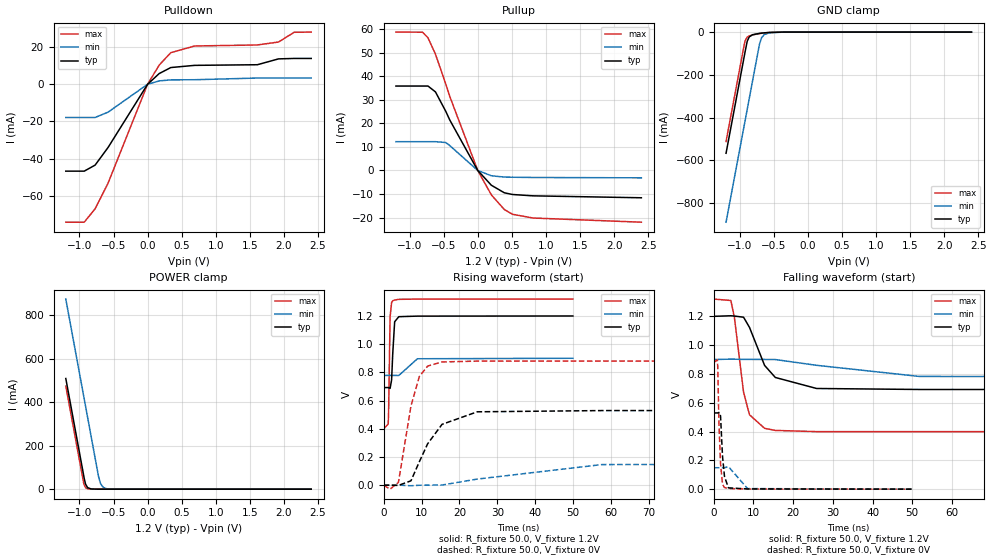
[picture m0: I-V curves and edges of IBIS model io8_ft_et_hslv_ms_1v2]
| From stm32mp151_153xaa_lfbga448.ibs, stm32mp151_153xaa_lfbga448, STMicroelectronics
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[Model]   io8_ft_et_hslv_ms_1v2
Model_type I/O
Polarity   Non-Inverting
Enable   Active-Low
| CAP_THRESHOLD on pad IOFT is "UDTCAPC" :
| Rising=20.00f vddiom   Falling=80.00f vddiom
| C_comp min and max val. don't necessarily correlate with the min and max pvt
| but are the smallest and greatest pad capacitance found.
| var   typ   min   max
C_comp   3.10945pF  3.08840pF  3.12935pF
|C_comp_pullup   1.82175pF  1.58940pF  1.75355pF
|C_comp_pulldown   1.28770pF  1.49900pF  1.37580pF
Vinl = 360.0mV
Vinh = 792.0mV
Vmeas = 600.0mV   | Reference voltage for timing measurements
Cref  = 50.0pF   | Timing specification test load capacitance value
Rref  = 100.0MOhm   | Timing specification test load resistance value
Vref  = 0V   | Timing specification test load voltage
[Model Spec]
| TIME_THRESHOLD on pin ZIV11 is "CMOS" :
| Rising=40.00f vdd   Falling=60.00f vdd
Vinl 463.60000mV 362.60000mV 506.60000mV
Vinh 741.40000mV 545.40000mV 817.40000mV
| variable   typ   min   max
[Temperature Range] 25.0 140.0 -40.0
| variable   typ   min   max
[Voltage Range] 1.2V 900.0mV 1.32V
| variable   typ   min   max
[POWER Clamp Reference] 1.2V 900.0mV 1.32V
| variable   typ   min   max
[GND Clamp Reference] 0V 0V 0V
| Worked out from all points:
|   slope of the pulldown table from 0 to 0.18 V, typ, clamps not added: 30 ohm
|   slope of the pullup table from 0 to 0.18 V, typ, clamps not added: 31.1 ohm
|   GND clamp passes 1 mA (typ) near -0.52 V on its own axis
|   POWER clamp passes 1 mA (typ) near -0.83 V on its own axis
|   rising waveform, R_fixture 50.0, V_fixture 1.2V: 20-80 % time 465ps typ, 1.29ns min, 300ps max; typ from 0.692 V to 1.2 V
|   falling waveform, R_fixture 50.0, V_fixture 1.2V: 20-80 % time 5.37ns typ, 13.1ns min, 2.71ns max; typ from 1.2 V to 0.692 V
|   rising waveform, R_fixture 50.0, V_fixture 0V: 20-80 % time 6.6ns typ, 15.4ns min, 3.56ns max; typ from 0 V to 0.529 V
|   falling waveform, R_fixture 50.0, V_fixture 0V: 20-80 % time 755ps typ, 1.48ns min, 602ps max; typ from 0.529 V to 0 V
[POWER Clamp]
-1.2V     508.8mA    874.1mA    473.5mA
-940mV    66.83mA    432.1mA    31.5mA
-930mV    49.83mA    415.1mA    19.15mA
-910mV    22.88mA    381.1mA    7.077mA
-880mV    7.117mA    330.1mA    1.59mA
-830mV    1.017mA    245.1mA    132uA
-720mV    14.05uA    58.12mA    554nA
-690mV    4.373uA    25.03mA    124.8nA
-650mV    922.5nA    8.136mA    17.23nA
-600mV    132.6nA    1.998mA    1.565nA
-490mV    2.857nA    90.92uA    111.8pA
2.4V      0A         0A         0A
[GND Clamp]
-1.2V     -567.2mA   -889.7mA   -512.2mA
-930mV    -108.2mA   -430.7mA   -53.23mA
-920mV    -91.21mA   -413.7mA   -40.49mA
-890mV    -43.51mA   -362.7mA   -23.59mA
-860mV    -22.57mA   -311.7mA   -17.89mA
-810mV    -12.11mA   -226.7mA   -13.23mA
-710mV    -6.053mA   -57.05mA   -7.064mA
-680mV    -4.908mA   -27.37mA   -5.632mA
-640mV    -3.605mA   -11.51mA   -3.985mA
-560mV    -1.665mA   -3.218mA   -1.61mA
-360mV    -34.72uA   -209.4uA   -9.248uA
2.4V      3.415nA    1.206uA    162.7pA
| variable   typ   min   max
[Pullup Reference] 1.2V 900.0mV 1.32V
| variable   typ   min   max
[Pulldown Reference] 0V 0V 0V
[Pullup]
-1.2V     35.8mA     12.19mA    58.69mA
-810mV    35.8mA     12.19mA    58.65mA
-730mV    35.8mA     12.19mA    56.27mA
-620mV    33.31mA    12.19mA    49.33mA
-470mV    25.13mA    11.85mA    36.73mA
-410mV    21.38mA    10.54mA    31.38mA
0V        5.9pA      1.254nA    2.839pA
200mV     -6.29mA    -2.269mA   -10.38mA
390mV     -9.484mA   -2.821mA   -16.59mA
510mV     -10.21mA   -2.888mA   -18.61mA
810mV     -10.78mA   -2.99mA    -20.19mA
2.4V      -11.6mA    -3.14mA    -21.96mA
[Pulldown]
-1.2V     -46.7mA    -17.86mA   -74.13mA
-930mV    -46.7mA    -17.86mA   -74.13mA
-770mV    -43.45mA   -17.86mA   -66.94mA
-580mV    -33.98mA   -14.99mA   -53.18mA
0V        0A         -6pA       0A
170mV     5.742mA    1.791mA    10.3mA
340mV     8.972mA    2.348mA    16.97mA
690mV     10.15mA    2.431mA    20.56mA
1.61V     10.49mA    3.333mA    21.11mA
1.92V     13.63mA    3.333mA    22.69mA
2.15V     13.87mA    3.333mA    27.93mA
2.4V      13.87mA    3.333mA    28.03mA
[Ramp]
dV/dt_r 317.40596mV/6.59553ns 89.2175mV/15.3922ns 528.1255mV/3.55691ns
dV/dt_f 304.66315mV/5.36712ns 73.16965mV/13.1332ns 552.41044mV/2.71068ns
R_load = 50.0
| Removed startup time: 0s 0s 0s  .
| Removed end time: 49.9ns.
[Rising Waveform]
R_fixture   = 50.0
V_fixture   = 1.2V
V_fixture_min = 900.0mV
V_fixture_max = 1.32V
0s        692.2mV    778mV      399.3mV
1.2ns     692.3mV    778.1mV    433.3mV
1.3ns     692.6mV    778.1mV    511.1mV
1.7ns     686.1mV    778.1mV    1.195V
2.1ns     747.2mV    778.1mV    1.296V
2.4ns     933.5mV    778.1mV    1.308V
2.9ns     1.159V     778.1mV    1.313V
4ns       1.195V     778mV      1.318V
8.9ns     1.199V     896.5mV    1.32V
49.9ns    1.2V       900mV      1.32V
| Removed startup time: 0s 0s 0s  .
| Removed end time: 299.9ns.
[Falling Waveform]
R_fixture   = 50.0
V_fixture   = 1.2V
V_fixture_min = 900.0mV
V_fixture_max = 1.32V
0s        1.2V       900mV      1.32V
4.3ns     1.204V     903mV      1.31V
5.2ns     1.202V     902.6mV    1.192V
7.5ns     1.194V     900.9mV    673mV
9ns       1.123V     901mV      516.6mV
12.8ns    859.3mV    900.7mV    422.3mV
15.5ns    775.6mV    900mV      407.9mV
25.9ns    699.1mV    860mV      399.5mV
51.8ns    692.2mV    782.7mV    399.3mV
299.9ns   692.2mV    778mV      399.3mV
| Removed startup time: 0s 0s 0s  .
| Removed end time: 299.9ns.
[Rising Waveform]
R_fixture   = 50.0
V_fixture   = 0V
V_fixture_min = 0V
V_fixture_max = 0V
0s        -85.77nV   237.3nV    -3.852uV
1.7ns     -652.7uV   362.2nV    -28.64mV
3.9ns     -1.908mV   141.5uV    19.39mV
7.2ns     30.56mV    -4.46mV    561.3mV
9.4ns     165.2mV    -926.5uV   770mV
11.6ns    293.1mV    96.9uV     844.4mV
15.4ns    431.3mV    770.9uV    873.9mV
24.7ns    520.2mV    43.02mV    879.9mV
57.6ns    528.9mV    146mV      880.2mV
299.9ns   529mV      148.7mV    880.2mV
| Removed startup time: 0s 0s 0s  .
| Removed end time: 49.9ns.
[Falling Waveform]
R_fixture   = 50.0
V_fixture   = 0V
V_fixture_min = 0V
V_fixture_max = 0V
0s        529mV      148.7mV    880.2mV
900ps     529.3mV    148.8mV    897.5mV
1ns       529.1mV    148.8mV    851.3mV
1.3ns     532.9mV    148.8mV    460.2mV
1.7ns     509.5mV    148.8mV    179.3mV
2.2ns     229.8mV    148.8mV    34.35mV
2.7ns     87.26mV    148.6mV    11.11mV
3.7ns     8.998mV    156.4mV    4.552mV
8.5ns     1.686mV    3.997mV    521.5uV
49.9ns    453.1nV    28.7uV     -108.1nV
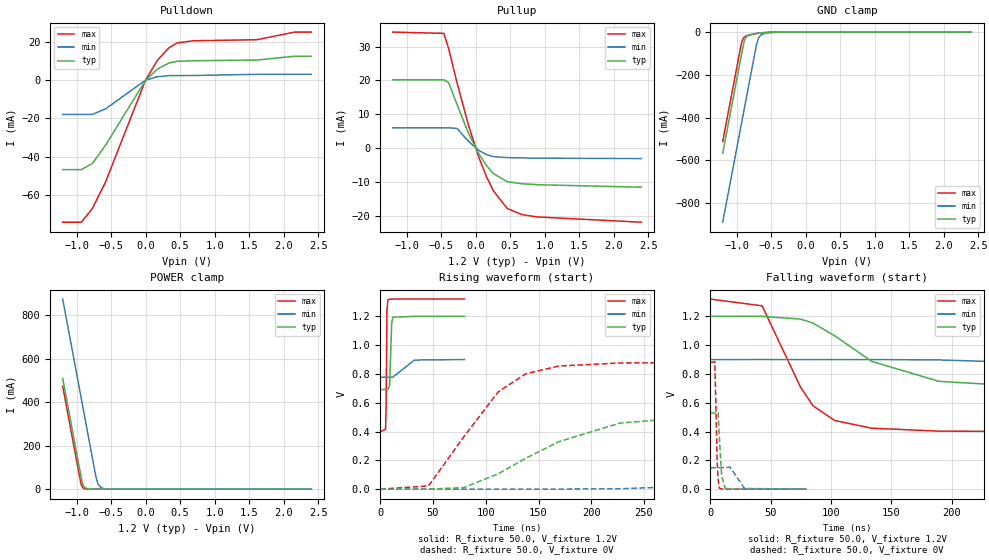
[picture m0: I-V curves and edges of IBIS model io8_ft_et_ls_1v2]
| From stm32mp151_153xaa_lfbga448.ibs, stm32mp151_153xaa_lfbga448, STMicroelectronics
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[Model]   io8_ft_et_ls_1v2
Model_type I/O
Polarity   Non-Inverting
Enable   Active-Low
| CAP_THRESHOLD on pad IOFT is "UDTCAPC" :
| Rising=20.00f vddiom   Falling=80.00f vddiom
| C_comp min and max val. don't necessarily correlate with the min and max pvt
| but are the smallest and greatest pad capacitance found.
| var   typ   min   max
C_comp   3.10945pF  3.08870pF  3.12935pF
|C_comp_pullup   1.82110pF  1.58850pF  1.75295pF
|C_comp_pulldown   1.28835pF  1.50020pF  1.37640pF
Vinl = 360.0mV
Vinh = 792.0mV
Vmeas = 600.0mV   | Reference voltage for timing measurements
Cref  = 50.0pF   | Timing specification test load capacitance value
Rref  = 100.0MOhm   | Timing specification test load resistance value
Vref  = 0V   | Timing specification test load voltage
[Model Spec]
| TIME_THRESHOLD on pin ZIV11 is "CMOS" :
| Rising=40.00f vdd   Falling=60.00f vdd
Vinl 463.60000mV 362.60000mV 506.60000mV
Vinh 741.40000mV 545.40000mV 817.40000mV
| variable   typ   min   max
[Temperature Range] 25.0 140.0 -40.0
| variable   typ   min   max
[Voltage Range] 1.2V 900.0mV 1.32V
| variable   typ   min   max
[POWER Clamp Reference] 1.2V 900.0mV 1.32V
| variable   typ   min   max
[GND Clamp Reference] 0V 0V 0V
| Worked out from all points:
|   slope of the pulldown table from 0 to 0.18 V, typ, clamps not added: 30 ohm
|   slope of the pullup table from 0 to 0.18 V, typ, clamps not added: 31.1 ohm
|   GND clamp passes 1 mA (typ) near -0.52 V on its own axis
|   POWER clamp passes 1 mA (typ) near -0.83 V on its own axis
|   rising waveform, R_fixture 50.0, V_fixture 1.2V: 20-80 % time 1.11ns typ, 3.32ns min, 567ps max; typ from 0.692 V to 1.2 V
|   falling waveform, R_fixture 50.0, V_fixture 1.2V: 20-80 % time 65.9ns typ, 198ns min, 31.1ns max; typ from 1.2 V to 0.692 V
|   rising waveform, R_fixture 50.0, V_fixture 0V: 20-80 % time 93.4ns typ, 229ns min, 52.8ns max; typ from 0 V to 0.529 V
|   falling waveform, R_fixture 50.0, V_fixture 0V: 20-80 % time 2.05ns typ, 4.72ns min, 1.45ns max; typ from 0.529 V to 0 V
[POWER Clamp]
-1.2V     508.8mA    874.1mA    473.5mA
-940mV    66.83mA    432.1mA    31.5mA
-930mV    49.83mA    415.1mA    19.15mA
-910mV    22.88mA    381.1mA    7.077mA
-880mV    7.117mA    330.1mA    1.59mA
-830mV    1.017mA    245.1mA    132uA
-720mV    14.05uA    58.12mA    554nA
-690mV    4.373uA    25.03mA    124.8nA
-650mV    922.5nA    8.136mA    17.23nA
-600mV    132.6nA    1.998mA    1.565nA
-490mV    2.858nA    90.92uA    111.8pA
2.4V      0A         0A         0A
[GND Clamp]
-1.2V     -567.2mA   -889.7mA   -512.2mA
-930mV    -108.2mA   -430.7mA   -53.23mA
-920mV    -91.21mA   -413.7mA   -40.49mA
-890mV    -43.51mA   -362.7mA   -23.59mA
-860mV    -22.57mA   -311.7mA   -17.89mA
-810mV    -12.11mA   -226.7mA   -13.23mA
-710mV    -6.053mA   -57.05mA   -7.064mA
-680mV    -4.908mA   -27.37mA   -5.632mA
-640mV    -3.605mA   -11.51mA   -3.985mA
-560mV    -1.665mA   -3.218mA   -1.61mA
-360mV    -34.72uA   -209.4uA   -9.248uA
2.4V      3.415nA    1.206uA    162.7pA
| variable   typ   min   max
[Pullup Reference] 1.2V 900.0mV 1.32V
| variable   typ   min   max
[Pulldown Reference] 0V 0V 0V
[Pullup]
-1.2V     20.17mA    5.956mA    34.28mA
-460mV    20.17mA    5.956mA    33.9mA
-390mV    19.33mA    5.956mA    29.41mA
-270mV    12.93mA    5.798mA    19.4mA
-100mV    4.223mA    1.913mA    6.531mA
50mV      -1.846mA   -759.1uA   -2.943mA
160mV     -5.268mA   -1.975mA   -8.606mA
260mV     -7.596mA   -2.574mA   -12.74mA
460mV     -9.999mA   -2.864mA   -17.94mA
670mV     -10.58mA   -2.95mA    -19.72mA
900mV     -10.88mA   -3.013mA   -20.42mA
2.4V      -11.6mA    -3.14mA    -21.96mA
[Pulldown]
-1.2V     -46.7mA    -17.86mA   -74.13mA
-930mV    -46.7mA    -17.86mA   -74.13mA
-770mV    -43.45mA   -17.86mA   -66.94mA
-580mV    -33.98mA   -14.99mA   -53.18mA
0V        0A         -8pA       0A
170mV     5.742mA    1.79mA     10.3mA
340mV     8.972mA    2.347mA    16.97mA
460mV     9.857mA    2.398mA    19.42mA
690mV     10.15mA    2.43mA     20.56mA
1.61V     10.49mA    3.049mA    21.11mA
2.16V     12.49mA    3.049mA    25.09mA
2.4V      12.49mA    3.049mA    25.09mA
[Ramp]
dV/dt_r 317.27049mV/93.36154ns 88.76397mV/229.06443ns 528.10754mV/52.7842ns
dV/dt_f 304.6737mV/65.87419ns 73.05802mV/185.00915ns 552.41033mV/31.05921ns
R_load = 50.0
| Removed startup time: 0s 0s 0s  .
| Removed end time: 79.9ns.
[Rising Waveform]
R_fixture   = 50.0
V_fixture   = 1.2V
V_fixture_min = 900.0mV
V_fixture_max = 1.32V
0s        692.2mV    778.1mV    399.3mV
5ns       692.2mV    778.1mV    414.8mV
5.5ns     692.2mV    778.1mV    557.4mV
6.3ns     692.3mV    778.1mV    1.241V
7.2ns     691.8mV    778.1mV    1.314V
8.9ns     720.7mV    778.1mV    1.319V
10.8ns    1.152V     778.1mV    1.319V
11.9ns    1.194V     778.1mV    1.32V
32.4ns    1.2V       896.5mV    1.32V
79.9ns    1.2V       899.9mV    1.32V
| Removed startup time: 0s 0s 0s  .
| Removed end time: 999.9ns.
[Falling Waveform]
R_fixture   = 50.0
V_fixture   = 1.2V
V_fixture_min = 900.0mV
V_fixture_max = 1.32V
0s        1.2V       900mV      1.32V
42.9ns    1.2V       900.1mV    1.273V
74.7ns    1.181V     900mV      708.7mV
85ns      1.153V     900mV      579mV
103ns     1.065V     900mV      476.8mV
133.7ns   887mV      899.9mV    423.2mV
189.4ns   748.5mV    897.6mV    402.9mV
291.9ns   698.9mV    870.1mV    399.4mV
555.6ns   692.2mV    789.3mV    399.3mV
999.9ns   692.2mV    778.2mV    399.3mV
| Removed startup time: 0s 0s 0s  .
| Removed end time: 999.9ns.
[Rising Waveform]
R_fixture   = 50.0
V_fixture   = 0V
V_fixture_min = 0V
V_fixture_max = 0V
0s        721.3nV    1.005uV    -323.9nV
45.7ns    -70.29uV   -14.83uV   22.22mV
79.3ns    11.13mV    -5.583uV   364.8mV
111.8ns   106.6mV    75.04uV    676mV
137.9ns   214.3mV    173.9uV    801.1mV
169ns     329.2mV    609.4uV    854.7mV
227ns     458.3mV    3.046mV    876.2mV
324.4ns   518mV      27.35mV    880mV
569.3ns   528.8mV    121.2mV    880.1mV
999.9ns   528.8mV    147.9mV    880.2mV
| Removed startup time: 0s 0s 0s  .
| Removed end time: 79.9ns.
[Falling Waveform]
R_fixture   = 50.0
V_fixture   = 0V
V_fixture_min = 0V
V_fixture_max = 0V
0s        529mV      148.8mV    880.2mV
3.8ns     529.1mV    148.8mV    884mV
5.7ns     531.7mV    148.8mV    197.2mV
6.5ns     534.3mV    148.8mV    70.29mV
7.5ns     364.6mV    148.8mV    6.247mV
9.4ns     93.3mV     148.8mV    1.22mV
12.4ns    2.492mV    148.7mV    396.2uV
16.4ns    382.4uV    153.4mV    269.7uV
28.3ns    116uV      5.025mV    252.1uV
79.9ns    151.2uV    28.46uV    63.33uV
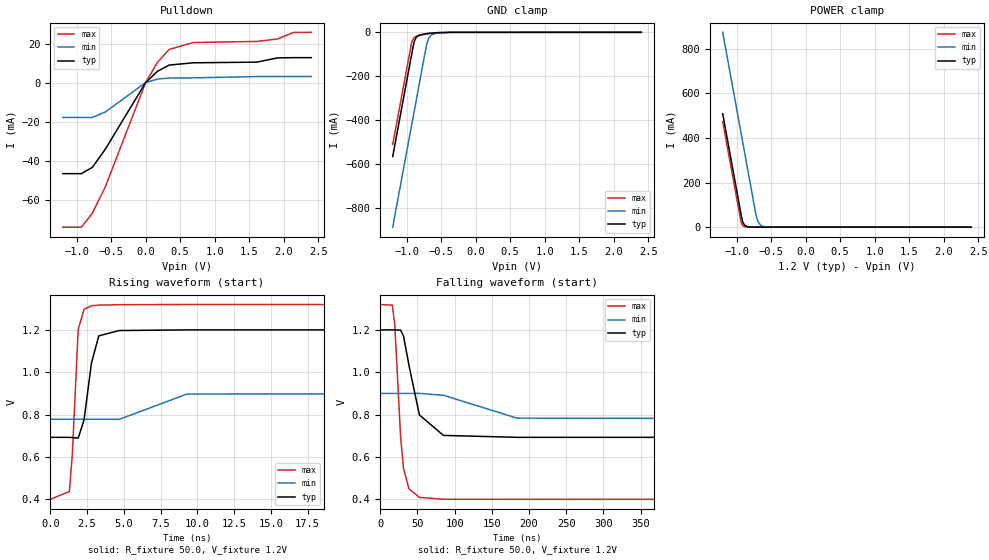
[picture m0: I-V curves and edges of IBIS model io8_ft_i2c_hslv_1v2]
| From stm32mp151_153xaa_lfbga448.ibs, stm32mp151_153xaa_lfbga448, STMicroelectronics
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[Model]   io8_ft_i2c_hslv_1v2
Model_type I/O_open_drain
Polarity   Non-Inverting
Enable   Active-Low
| CAP_THRESHOLD on pad IOFT is "UDTCAPC" :
| Rising=20.00f vddiom   Falling=80.00f vddiom
| C_comp min and max val. don't necessarily correlate with the min and max pvt
| but are the smallest and greatest pad capacitance found.
| var   typ   min   max
C_comp   3.10390pF  3.08145pF  3.12355pF
|C_comp_pulldown   3.10390pF  3.08145pF  3.12355pF
Vinl = 360.0mV
Vinh = 792.0mV
Vmeas = 600.0mV   | Reference voltage for timing measurements
Cref  = 50.0pF   | Timing specification test load capacitance value
Rref  = 100.0MOhm   | Timing specification test load resistance value
Vref  = 600.0mV   | Timing specification test load voltage
[Model Spec]
| TIME_THRESHOLD on pin ZIV11 is "CMOS" :
| Rising=40.00f vdd   Falling=60.00f vdd
Vinl 463.60000mV 362.60000mV 506.60000mV
Vinh 742.40000mV 546.40000mV 818.40000mV
| variable   typ   min   max
[Temperature Range] 25.0 140.0 -40.0
| variable   typ   min   max
[Voltage Range] 1.2V 900.0mV 1.32V
| variable   typ   min   max
[POWER Clamp Reference] 1.2V 900.0mV 1.32V
| variable   typ   min   max
[GND Clamp Reference] 0V 0V 0V
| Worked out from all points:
|   slope of the pulldown table from 0 to 0.18 V, typ, clamps not added: 30 ohm
|   GND clamp passes 1 mA (typ) near -0.52 V on its own axis
|   POWER clamp passes 1 mA (typ) near -0.83 V on its own axis
|   rising waveform, R_fixture 50.0, V_fixture 1.2V: 20-80 % time 595ps typ, 1.61ns min, 348ps max; typ from 0.692 V to 1.2 V
|   falling waveform, R_fixture 50.0, V_fixture 1.2V: 20-80 % time 17.4ns typ, 43.1ns min, 8.86ns max; typ from 1.2 V to 0.692 V
[POWER Clamp]
-1.2V     508.8mA    874.1mA    473.5mA
-940mV    66.83mA    432.1mA    31.5mA
-930mV    49.83mA    415.1mA    19.15mA
-910mV    22.88mA    381.1mA    7.077mA
-880mV    7.117mA    330.1mA    1.59mA
-830mV    1.017mA    245.1mA    132uA
-720mV    14.05uA    58.12mA    554nA
-690mV    4.373uA    25.03mA    124.7nA
-650mV    922.4nA    8.136mA    17.22nA
-600mV    132.5nA    1.998mA    1.555nA
-490mV    2.736nA    90.9uA     103pA
2.4V      0A         0A         0A
[GND Clamp]
-1.2V     -567.2mA   -889.7mA   -512.2mA
-930mV    -108.2mA   -430.7mA   -53.23mA
-920mV    -91.21mA   -413.7mA   -40.49mA
-890mV    -43.51mA   -362.7mA   -23.59mA
-860mV    -22.57mA   -311.7mA   -17.89mA
-810mV    -12.11mA   -226.7mA   -13.23mA
-710mV    -6.053mA   -57.05mA   -7.064mA
-680mV    -4.908mA   -27.37mA   -5.632mA
-640mV    -3.605mA   -11.51mA   -3.985mA
-560mV    -1.665mA   -3.218mA   -1.61mA
-360mV    -34.72uA   -209.4uA   -9.248uA
2.4V      3.381nA    1.198uA    162.5pA
| variable   typ   min   max
[Pullup Reference] 1.2V 900.0mV 1.32V
| variable   typ   min   max
[Pulldown Reference] 0V 0V 0V
[Pulldown]
-1.2V     -46.7mA    -17.86mA   -74.13mA
-930mV    -46.7mA    -17.86mA   -74.13mA
-770mV    -43.45mA   -17.86mA   -66.94mA
-580mV    -33.98mA   -14.99mA   -53.18mA
0V        0A         -3pA       0A
170mV     5.742mA    1.791mA    10.3mA
340mV     8.972mA    2.348mA    16.97mA
690mV     10.15mA    2.43mA     20.56mA
1.61V     10.49mA    3.107mA    21.11mA
1.91V     12.66mA    3.107mA    22.36mA
2.14V     12.8mA     3.107mA    25.73mA
2.4V      12.8mA     3.107mA    25.78mA
[Ramp]
dV/dt_r 304.65337mV/587.88729ps 73.15526mV/1.60827ns 552.40224mV/338.51701ps
dV/dt_f 304.67839mV/17.3827ns 73.17138mV/43.0695ns 552.41148mV/8.86135ns
R_load = 50.0
| Removed startup time: 0s 0s 0s  .
| Removed end time: 59.9ns.
[Rising Waveform]
R_fixture   = 50.0
V_fixture   = 1.2V
V_fixture_min = 900.0mV
V_fixture_max = 1.32V
0s        692.2mV    778.1mV    399.3mV
1.3ns     692.2mV    778mV      436.3mV
1.5ns     691.1mV    778.1mV    613.5mV
1.9ns     688.7mV    778.1mV    1.203V
2.3ns     775.9mV    778.1mV    1.297V
2.8ns     1.043V     778.1mV    1.314V
3.3ns     1.172V     778mV      1.317V
4.7ns     1.197V     777.4mV    1.319V
9.3ns     1.2V       897mV      1.32V
59.9ns    1.2V       900mV      1.32V
| Removed startup time: 0s 0s 0s  .
| Removed end time: 999.9ns.
[Falling Waveform]
R_fixture   = 50.0
V_fixture   = 1.2V
V_fixture_min = 900.0mV
V_fixture_max = 1.32V
0s        1.2V       900mV      1.32V
16.2ns    1.2V       900mV      1.317V
19.5ns    1.2V       900mV      1.224V
27.3ns    1.199V     900mV      695.4mV
31.2ns    1.172V     899.9mV    546.2mV
38.6ns    1.032V     900mV      448.6mV
52.6ns    798mV      900mV      408.5mV
84.9ns    701.4mV    891.1mV    399.6mV
183.8ns   692.3mV    783mV      399.3mV
999.9ns   692.2mV    778mV      399.3mV
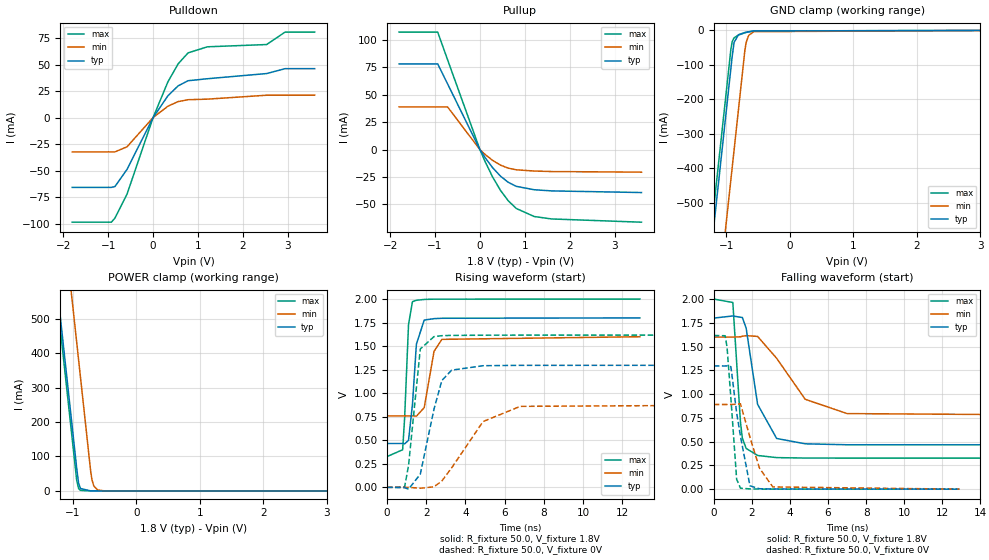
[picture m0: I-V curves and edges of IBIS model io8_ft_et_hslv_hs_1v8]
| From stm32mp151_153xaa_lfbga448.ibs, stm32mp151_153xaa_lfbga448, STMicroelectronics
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[Model]   io8_ft_et_hslv_hs_1v8
Model_type I/O
Polarity   Non-Inverting
Enable   Active-Low
| CAP_THRESHOLD on pad IOFT is "UDTCAPC" :
| Rising=20.00f vddiom   Falling=80.00f vddiom
| C_comp min and max val. don't necessarily correlate with the min and max pvt
| but are the smallest and greatest pad capacitance found.
| var   typ   min   max
C_comp   3.43098pF  3.42356pF  3.49920pF
|C_comp_pullup   1.96775pF  2.05990pF  1.91900pF
|C_comp_pulldown   1.46323pF  1.36366pF  1.58020pF
Vinl = 640.0mV
Vinh = 1.2V
Vmeas = 900.0mV   | Reference voltage for timing measurements
Cref  = 50.0pF   | Timing specification test load capacitance value
Rref  = 100.0MOhm   | Timing specification test load resistance value
Vref  = 0V   | Timing specification test load voltage
[Model Spec]
| TIME_THRESHOLD on pin ZIV11 is "CMOS" :
| Rising=40.00f vdd   Falling=60.00f vdd
Vinl 738.60000mV 665.60000mV 824.60000mV
Vinh 1.04640V 924.40000mV 1.13940V
| variable   typ   min   max
[Temperature Range] 25.0 140.0 -40.0
| variable   typ   min   max
[Voltage Range] 1.8V 1.6V 2.0V
| variable   typ   min   max
[POWER Clamp Reference] 1.8V 1.6V 2.0V
| variable   typ   min   max
[GND Clamp Reference] 0V 0V 0V
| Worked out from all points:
|   slope of the pulldown table from 0 to 0.27 V, typ, clamps not added: 16 ohm
|   slope of the pullup table from 0 to 0.27 V, typ, clamps not added: 17 ohm
|   GND clamp passes 1 mA (typ) near -0.52 V on its own axis
|   POWER clamp passes 1 mA (typ) near -0.83 V on its own axis
|   rising waveform, R_fixture 50.0, V_fixture 1.8V: 20-80 % time 264ps typ, 402ps min, 207ps max; typ from 0.466 V to 1.8 V
|   falling waveform, R_fixture 50.0, V_fixture 1.8V: 20-80 % time 683ps typ, 1.76ns min, 311ps max; typ from 1.8 V to 0.466 V
|   rising waveform, R_fixture 50.0, V_fixture 0V: 20-80 % time 794ps typ, 1.76ns min, 423ps max; typ from 0 V to 1.3 V
|   falling waveform, R_fixture 50.0, V_fixture 0V: 20-80 % time 552ps typ, 788ps min, 347ps max; typ from 1.3 V to 0 V
[POWER Clamp]
-1.8V     1.529A     1.894A     1.494A
-940mV    66.83mA    432.1mA    31.5mA
-910mV    22.88mA    381.1mA    7.077mA
-880mV    7.117mA    330.1mA    1.59mA
-720mV    14.05uA    58.12mA    554nA
-700mV    6.453uA    33.14mA    205nA
-670mV    2.008uA    14.27mA    46.29nA
-610mV    195.5nA    2.645mA    2.508nA
-500mV    3.96nA     120.4uA    139.7pA
3.6V      0A         0A         0A
[GND Clamp]
-1.8V     -1.588A    -1.91A     -1.533A
-1.26V    -670.3mA   -992.4mA   -614.9mA
-1.2V     -568.3mA   -890.4mA   -512.9mA
-930mV    -109.3mA   -431.4mA   -53.86mA
-910mV    -75.33mA   -397.4mA   -32.91mA
-880mV    -34.88mA   -346.4mA   -21.56mA
-810mV    -12.56mA   -227.4mA   -13.55mA
-710mV    -6.275mA   -57.63mA   -7.234mA
-690mV    -5.461mA   -35.21mA   -6.234mA
-650mV    -4.039mA   -14.43mA   -4.463mA
-570mV    -1.908mA   -3.832mA   -1.869mA
3.6V      5.084nA    1.599uA    245.6pA
| variable   typ   min   max
[Pullup Reference] 1.8V 1.6V 2.0V
| variable   typ   min   max
[Pulldown Reference] 0V 0V 0V
[Pullup]
-1.8V     78.15mA    38.89mA    107.2mA
-940mV    78.15mA    38.89mA    107.2mA
-720mV    59.96mA    38.89mA    81.97mA
0V        7.41pA     1.331nA    4.294pA
110mV     -7.005mA   -4.277mA   -10.45mA
280mV     -16.39mA   -9.815mA   -24.79mA
460mV     -24.33mA   -14.23mA   -37.36mA
630mV     -29.85mA   -16.98mA   -46.66mA
810mV     -33.57mA   -18.49mA   -53.77mA
1.21V     -36.68mA   -19.61mA   -61.13mA
1.6V      -37.75mA   -20.08mA   -63.35mA
3.6V      -39.24mA   -20.63mA   -66.3mA
[Pulldown]
-1.8V     -65.8mA    -32.31mA   -98.64mA
-930mV    -65.8mA    -32.31mA   -98.64mA
-850mV    -65.04mA   -32.31mA   -94.81mA
-580mV    -48.83mA   -27.49mA   -72.14mA
0V        0A         -3pA       0A
330mV     20.59mA    10.79mA    33.74mA
560mV     30.02mA    15.15mA    50.81mA
780mV     34.81mA    16.9mA     61.1mA
1.21V     36.69mA    17.44mA    66.81mA
2.53V     41.58mA    21.14mA    68.95mA
2.94V     46.18mA    21.14mA    80.69mA
3.6V      46.18mA    21.14mA    80.69mA
[Ramp]
dV/dt_r 777.92293mV/789.75552ps 534.23402mV/1.76209ns 970.12525mV/416.81061ps
dV/dt_f 800.59754mV/682.02744ps 504.71918mV/1.76039ns 1.00395V/302.68207ps
R_load = 50.0
| Removed startup time: 0s 0s 0s  .
| Removed end time: 12.9ns.
[Rising Waveform]
R_fixture   = 50.0
V_fixture   = 1.8V
V_fixture_min = 1.6V
V_fixture_max = 2.0V
0s        465.7mV    758.8mV    326.7mV
800ps     465.7mV    759mV      399.2mV
900ps     462mV      759mV      733.9mV
1.1ns     499.3mV    759mV      1.73V
1.3ns     879.4mV    759.5mV    1.972V
1.5ns     1.52V      755.5mV    1.987V
1.9ns     1.777V     847mV      1.996V
2.4ns     1.792V     1.444V     1.999V
2.8ns     1.796V     1.572V     1.999V
12.9ns    1.8V       1.6V       2V
| Removed startup time: 0s 0s 0s  .
| Removed end time: 34.9ns.
[Falling Waveform]
R_fixture   = 50.0
V_fixture   = 1.8V
V_fixture_min = 1.6V
V_fixture_max = 2.0V
0s        1.8V       1.6V       2V
1ns       1.822V     1.6V       1.964V
1.4ns     1.809V     1.603V     706.7mV
1.5ns     1.806V     1.609V     536.3mV
1.7ns     1.694V     1.615V     428.5mV
2.3ns     893mV      1.607V     354.5mV
3.3ns     533.4mV    1.377V     332mV
4.8ns     477.2mV    945.7mV    327.4mV
7ns       467.1mV    795.1mV    326.8mV
34.9ns    465.7mV    758.8mV    326.8mV
| Removed startup time: 0s 0s 0s  .
| Removed end time: 34.9ns.
[Rising Waveform]
R_fixture   = 50.0
V_fixture   = 0V
V_fixture_min = 0V
V_fixture_max = 0V
0s        -4.041nV   -345.2nV   -5.215uV
900ps     -3.239mV   -30.49uV   4.816mV
1.1ns     -19.37mV   -153.5uV   231.3mV
1.7ns     140mV      -9.572mV   1.47V
2.4ns     832.1mV    5.628mV    1.601V
2.8ns     1.135V     67.22mV    1.611V
3.3ns     1.245V     206.9mV    1.614V
4.9ns     1.292V     698.9mV    1.616V
6.8ns     1.296V     860.4mV    1.617V
34.9ns    1.297V     890.4mV    1.617V
| Removed startup time: 0s 0s 0s  .
| Removed end time: 12.9ns.
[Falling Waveform]
R_fixture   = 50.0
V_fixture   = 0V
V_fixture_min = 0V
V_fixture_max = 0V
0s        1.297V     890.4mV    1.617V
600ps     1.296V     890.5mV    1.614V
700ps     1.298V     890.5mV    1.488V
900ps     1.288V     890.5mV    952.4mV
1.2ns     803.8mV    893.8mV    105.1mV
1.4ns     557.4mV    898.4mV    10.7mV
1.9ns     35.24mV    545.7mV    2.687mV
2.4ns     4.432mV    220.4mV    1.305mV
3.1ns     1.899mV    23.45mV    524.5uV
12.9ns    16.47uV    38.25uV    5.954uV
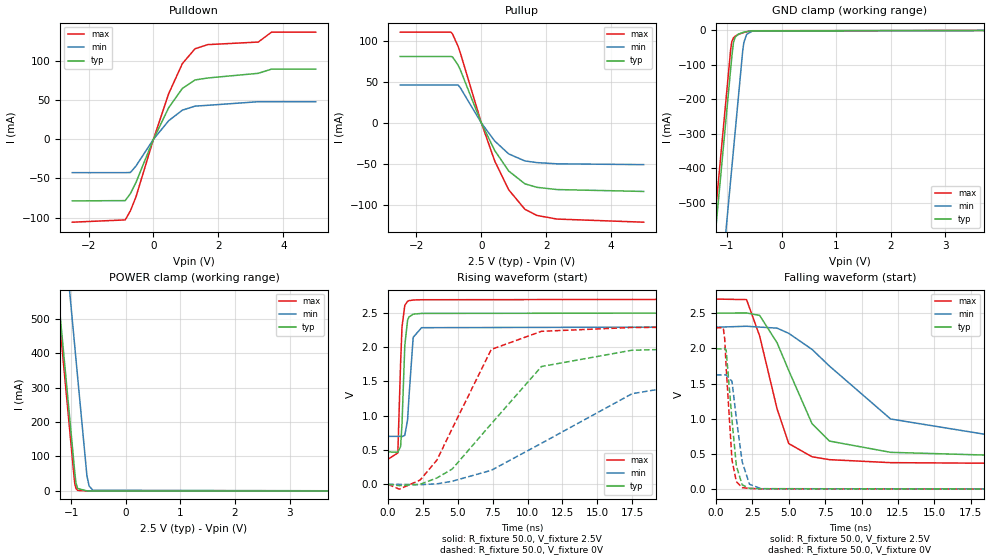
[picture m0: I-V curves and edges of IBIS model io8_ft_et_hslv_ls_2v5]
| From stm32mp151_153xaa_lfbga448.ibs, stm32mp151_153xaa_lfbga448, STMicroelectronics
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[Model]   io8_ft_et_hslv_ls_2v5
Model_type I/O
Polarity   Non-Inverting
Enable   Active-Low
| CAP_THRESHOLD on pad IOFT is "UDTCAPC" :
| Rising=20.00f vddiom   Falling=80.00f vddiom
| C_comp min and max val. don't necessarily correlate with the min and max pvt
| but are the smallest and greatest pad capacitance found.
| var   typ   min   max
C_comp   3.59839pF  3.56215pF  3.65635pF
|C_comp_pullup   2.12240pF  2.18495pF  2.03935pF
|C_comp_pulldown   1.47599pF  1.37720pF  1.61700pF
Vinl = 920.0mV
Vinh = 1.62V
Vmeas = 1.25V   | Reference voltage for timing measurements
Cref  = 50.0pF   | Timing specification test load capacitance value
Rref  = 100.0MOhm   | Timing specification test load resistance value
Vref  = 0V   | Timing specification test load voltage
[Model Spec]
| TIME_THRESHOLD on pin ZIV11 is "CMOS" :
| Rising=40.00f vdd   Falling=60.00f vdd
Vinl 1.03860V 964.60000mV 1.11860V
Vinh 1.36340V 1.26240V 1.44140V
| variable   typ   min   max
[Temperature Range] 25.0 140.0 -40.0
| variable   typ   min   max
[Voltage Range] 2.5V 2.3V 2.7V
| variable   typ   min   max
[POWER Clamp Reference] 2.5V 2.3V 2.7V
| variable   typ   min   max
[GND Clamp Reference] 0V 0V 0V
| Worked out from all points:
|   slope of the pulldown table from 0 to 0.375 V, typ, clamps not added: 11.3 ohm
|   slope of the pullup table from 0 to 0.375 V, typ, clamps not added: 12.3 ohm
|   GND clamp passes 1 mA (typ) near -0.52 V on its own axis
|   POWER clamp passes 1 mA (typ) near -0.83 V on its own axis
|   rising waveform, R_fixture 50.0, V_fixture 2.5V: 20-80 % time 229ps typ, 271ps min, 228ps max; typ from 0.473 V to 2.5 V
|   falling waveform, R_fixture 50.0, V_fixture 2.5V: 20-80 % time 2.59ns typ, 5.13ns min, 1.7ns max; typ from 2.5 V to 0.473 V
|   rising waveform, R_fixture 50.0, V_fixture 0V: 20-80 % time 4.72ns typ, 8.56ns min, 3.15ns max; typ from 0 V to 1.99 V
|   falling waveform, R_fixture 50.0, V_fixture 0V: 20-80 % time 492ps typ, 633ps min, 408ps max; typ from 1.99 V to 0 V
[POWER Clamp]
-2.5V     2.719A     3.084A     2.683A
-1.38V    814.8mA    1.18A      779.5mA
-1.28V    644.8mA    1.01A      609.5mA
-1.07V    287.8mA    653.1mA    252.5mA
-940mV    66.83mA    432.1mA    31.5mA
-930mV    49.83mA    415.1mA    19.15mA
-910mV    22.88mA    381.1mA    7.077mA
-880mV    7.117mA    330.1mA    1.59mA
-710mV    9.523uA    43.89mA    337nA
-670mV    2.009uA    14.27mA    46.32nA
-600mV    133.1nA    1.998mA    1.613nA
5V        0A         0A         0A
[GND Clamp]
-2.5V     -2.779A    -3.101A    -2.723A
-1.26V    -670.8mA   -992.7mA   -614.5mA
-930mV    -109.8mA   -431.7mA   -53.54mA
-910mV    -75.83mA   -397.7mA   -32.67mA
-880mV    -35.28mA   -346.7mA   -21.39mA
-850mV    -20.07mA   -295.7mA   -16.99mA
-790mV    -10.9mA    -193.7mA   -12.02mA
-710mV    -6.374mA   -57.93mA   -7.219mA
-690mV    -5.545mA   -35.45mA   -6.225mA
-640mV    -3.775mA   -11.96mA   -4.068mA
-540mV    -1.354mA   -2.661mA   -1.223mA
5V        7.033nA    2.148uA    347.4pA
| variable   typ   min   max
[Pullup Reference] 2.5V 2.3V 2.7V
| variable   typ   min   max
[Pulldown Reference] 0V 0V 0V
[Pullup]
-2.5V     80.79mA    46.14mA    110.4mA
-940mV    80.79mA    46.14mA    110.4mA
-890mV    80.23mA    46.14mA    108.2mA
-720mV    70.48mA    46.14mA    93.32mA
-650mV    64.61mA    42.86mA    85.27mA
0V        9.19pA     1.4nA      5.79pA
410mV     -33.27mA   -21.81mA   -45.98mA
840mV     -58.2mA    -37.46mA   -80.99mA
1.34V     -73.8mA    -46.03mA   -104.7mA
1.71V     -78.05mA   -48.05mA   -112.2mA
2.33V     -80.79mA   -49.54mA   -116.6mA
5V        -83.07mA   -50.51mA   -120.4mA
[Pulldown]
-2.5V     -78.63mA   -42.6mA    -105.8mA
-870mV    -78.28mA   -42.6mA    -102.9mA
-710mV    -69.32mA   -42.37mA   -91.24mA
-540mV    -55.23mA   -34.22mA   -73.64mA
0V        0A         -3pA       10fA
470mV     40.29mA    23.69mA    58.27mA
890mV     64.85mA    37.11mA    96.49mA
1.28V     75.62mA    42.24mA    115.4mA
1.67V     78.14mA    43.3mA     120.7mA
3.23V     84.11mA    47.88mA    124mA
3.64V     89.51mA    47.88mA    136.7mA
5V        89.51mA    47.88mA    136.7mA
[Ramp]
dV/dt_r 1.19557V/4.72113ns 973.54476mV/8.5553ns 1.37498V/3.15119ns
dV/dt_f 1.21605V/2.58387ns 960.46504mV/5.13037ns 1.39952V/1.70037ns
R_load = 50.0
| Removed startup time: 0s 0s 0s  .
| Removed end time: 37.9ns.
[Rising Waveform]
R_fixture   = 50.0
V_fixture   = 2.5V
V_fixture_min = 2.3V
V_fixture_max = 2.7V
0s        473.2mV    699.2mV    367.5mV
700ps     467.3mV    699.1mV    456.9mV
900ps     552.5mV    699.5mV    1.776V
1ns       885.7mV    695.1mV    2.294V
1.2ns     2.024V     715mV      2.608V
1.4ns     2.393V     941.2mV    2.667V
1.5ns     2.439V     1.276V     2.677V
1.8ns     2.48V      2.142V     2.686V
2.4ns     2.491V     2.283V     2.69V
37.9ns    2.5V       2.3V       2.7V
| Removed startup time: 0s 0s 0s  .
| Removed end time: 89.9ns.
[Falling Waveform]
R_fixture   = 50.0
V_fixture   = 2.5V
V_fixture_min = 2.3V
V_fixture_max = 2.7V
0s        2.5V       2.3V       2.7V
2.1ns     2.503V     2.314V     2.692V
3ns       2.468V     2.302V     2.176V
4.2ns     2.078V     2.287V     1.139V
5ns       1.685V     2.213V     647.5mV
6.6ns     929.4mV    1.985V     459.8mV
7.8ns     683mV      1.748V     419.1mV
12ns      523.2mV    996.5mV    376.6mV
18.8ns    482.4mV    768.7mV    368.3mV
89.9ns    473.2mV    699.2mV    367.5mV
| Removed startup time: 0s 0s 0s  .
| Removed end time: 89.9ns.
[Rising Waveform]
R_fixture   = 50.0
V_fixture   = 0V
V_fixture_min = 0V
V_fixture_max = 0V
0s        232.4nV    -232.9nV   -5.892uV
800ps     -18.37mV   -51.4uV    -70.16mV
2.3ns     807.4uV    -4.782mV   62.98mV
3.5ns     92.94mV    7.551mV    352.9mV
4.6ns     222.9mV    45.19mV    813.3mV
7.4ns     882.4mV    204.7mV    1.966V
11ns      1.717V     598.5mV    2.23V
17.5ns    1.955V     1.321V     2.286V
24.1ns    1.986V     1.544V     2.291V
89.9ns    1.993V     1.623V     2.292V
| Removed startup time: 0s 0s 0s  .
| Removed end time: 37.9ns.
[Falling Waveform]
R_fixture   = 50.0
V_fixture   = 0V
V_fixture_min = 0V
V_fixture_max = 0V
0s        1.993V     1.623V     2.292V
500ps     1.993V     1.623V     2.292V
600ps     2.002V     1.623V     2.134V
700ps     1.972V     1.622V     1.728V
1.1ns     981.9mV    1.531V     414.1mV
1.4ns     329.9mV    1.004V     106.1mV
1.8ns     61.55mV    389mV      22.8mV
2.3ns     11.66mV    70.48mV    10.35mV
3.1ns     6.511mV    6.571mV    4.853mV
37.9ns    -6.588nV   17.07uV    4.538uV
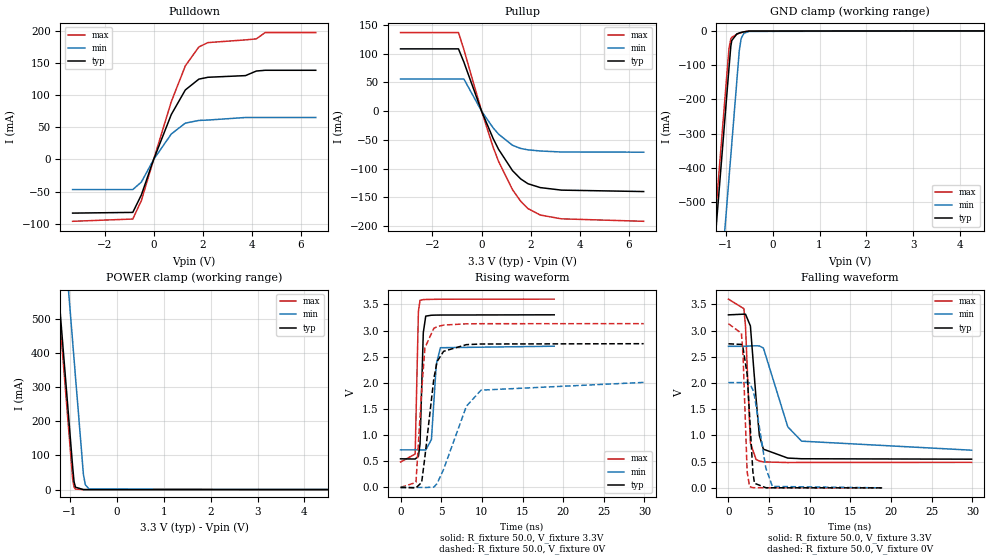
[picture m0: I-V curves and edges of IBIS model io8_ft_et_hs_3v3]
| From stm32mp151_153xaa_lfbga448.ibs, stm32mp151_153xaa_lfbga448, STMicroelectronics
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[Model]   io8_ft_et_hs_3v3
Model_type I/O
Polarity   Non-Inverting
Enable   Active-Low
| CAP_THRESHOLD on pad IOFT is "UDTCAPC" :
| Rising=20.00f vddiom   Falling=80.00f vddiom
| C_comp min and max val. don't necessarily correlate with the min and max pvt
| but are the smallest and greatest pad capacitance found.
| var   typ   min   max
C_comp   3.68632pF  3.64973pF  3.70800pF
|C_comp_pullup   2.21620pF  2.27950pF  2.11835pF
|C_comp_pulldown   1.47012pF  1.37023pF  1.58965pF
Vinl = 1.08V
Vinh = 2.16V
Vmeas = 1.65V   | Reference voltage for timing measurements
Cref  = 50.0pF   | Timing specification test load capacitance value
Rref  = 100.0MOhm   | Timing specification test load resistance value
Vref  = 0V   | Timing specification test load voltage
[Model Spec]
| TIME_THRESHOLD on pin ZIV11 is "CMOS" :
| Rising=40.00f vdd   Falling=60.00f vdd
Vinl 1.36060V 1.12960V 1.47360V
Vinh 1.71540V 1.45040V 1.82940V
| variable   typ   min   max
[Temperature Range] 25.0 140.0 -40.0
| variable   typ   min   max
[Voltage Range] 3.3V 2.7V 3.6V
| variable   typ   min   max
[POWER Clamp Reference] 3.3V 2.7V 3.6V
| variable   typ   min   max
[GND Clamp Reference] 0V 0V 0V
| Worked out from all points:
|   slope of the pulldown table from 0 to 0.495 V, typ, clamps not added: 9.86 ohm
|   slope of the pullup table from 0 to 0.495 V, typ, clamps not added: 9.93 ohm
|   GND clamp passes 1 mA (typ) near -0.52 V on its own axis
|   POWER clamp passes 1 mA (typ) near -0.83 V on its own axis
|   rising waveform, R_fixture 50.0, V_fixture 3.3V: 20-80 % time 289ps typ, 431ps min, 228ps max; typ from 0.547 V to 3.3 V
|   falling waveform, R_fixture 50.0, V_fixture 3.3V: 20-80 % time 789ps typ, 2.17ns min, 483ps max; typ from 3.3 V to 0.547 V
|   rising waveform, R_fixture 50.0, V_fixture 0V: 20-80 % time 1.24ns typ, 2.84ns min, 749ps max; typ from 0 V to 2.75 V
|   falling waveform, R_fixture 50.0, V_fixture 0V: 20-80 % time 615ps typ, 1.18ns min, 414ps max; typ from 2.75 V to 0 V
[POWER Clamp]
-3.3V     4.079A     4.444A     4.043A
-1.46V    950.8mA    1.316A     915.5mA
-1.28V    644.8mA    1.01A      609.5mA
-1.09V    321.8mA    687.1mA    286.5mA
-1.07V    287.8mA    653.1mA    252.5mA
-940mV    66.83mA    432.1mA    31.5mA
-910mV    22.88mA    381.1mA    7.077mA
-880mV    7.117mA    330.1mA    1.59mA
-710mV    9.525uA    43.89mA    337.5nA
-670mV    2.01uA     14.27mA    46.79nA
-590mV    92.5nA     1.508mA    1.514nA
6.6V      0A         0A         0A
[GND Clamp]
-3.3V     -4.139A    -4.461A    -4.081A
-1.26V    -670.8mA   -992.8mA   -613.3mA
-1.1V     -398.8mA   -720.8mA   -341.3mA
-930mV    -109.8mA   -431.8mA   -52.32mA
-890mV    -44.91mA   -363.8mA   -23.04mA
-870mV    -28.43mA   -329.8mA   -18.86mA
-760mV    -8.879mA   -142.8mA   -9.749mA
-710mV    -6.383mA   -58.04mA   -7.036mA
-670mV    -4.798mA   -22.41mA   -5.193mA
-610mV    -2.902mA   -7.057mA   -2.962mA
-500mV    -778.4uA   -1.643mA   -611.3uA
6.6V      9.268nA    3.087uA    468pA
| variable   typ   min   max
[Pullup Reference] 3.3V 2.7V 3.6V
| variable   typ   min   max
[Pulldown Reference] 0V 0V 0V
[Pullup]
-3.3V     108.4mA    55.88mA    136.8mA
-940mV    108.4mA    55.88mA    136.8mA
-720mV    85.29mA    55.88mA    107.1mA
0V        11.24pA    1.438nA    7.78pA
470mV     -47.64mA   -29.17mA   -62.71mA
690mV     -66.39mA   -40.06mA   -87.4mA
1.26V     -103.7mA   -59.49mA   -136.9mA
1.59V     -118mA     -65.02mA   -156.8mA
1.89V     -126.5mA   -67.46mA   -169.8mA
2.39V     -133.2mA   -69.44mA   -181mA
3.25V     -137.6mA   -71.22mA   -187.6mA
6.6V      -140.1mA   -71.49mA   -191.9mA
[Pulldown]
-3.3V     -83.56mA   -46.9mA    -96.31mA
-850mV    -82.46mA   -46.9mA    -92.78mA
-500mV    -55.19mA   -35.23mA   -63.97mA
0V        30fA       -2pA       200fA
720mV     70.07mA    39.69mA    90.11mA
1.29V     108.2mA    56.55mA    145.7mA
1.84V     125mA      60.7mA     175.1mA
2.21V     127.9mA    61.3mA     181.9mA
3.74V     130.5mA    65.29mA    186.1mA
4.18V     137.6mA    65.29mA    187.7mA
4.54V     138.8mA    65.29mA    197.5mA
6.6V      138.8mA    65.29mA    197.5mA
[Ramp]
dV/dt_r 1.64855V/1.23455ns 1.20466V/2.83438ns 1.87852V/749.37133ps
dV/dt_f 1.65162V/783.39378ps 1.18883V/2.1655ns 1.86819V/476.2589ps
R_load = 50.0
| Removed startup time: 0s 0s 0s  .
| Removed end time: 18.9ns.
[Rising Waveform]
R_fixture   = 50.0
V_fixture   = 3.3V
V_fixture_min = 2.7V
V_fixture_max = 3.6V
0s        547.3mV    718.4mV    486.3mV
1.8ns     543.5mV    718.4mV    638.1mV
2.2ns     595.8mV    718.4mV    3.367V
2.4ns     830.9mV    718.4mV    3.577V
2.8ns     2.958V     717.9mV    3.591V
3.1ns     3.275V     716.7mV    3.593V
3.8ns     3.292V     916.1mV    3.596V
4.4ns     3.295V     2.358V     3.597V
4.9ns     3.296V     2.671V     3.598V
18.9ns    3.3V       2.7V       3.6V
| Removed startup time: 0s 0s 0s  .
| Removed end time: 29.9ns.
[Falling Waveform]
R_fixture   = 50.0
V_fixture   = 3.3V
V_fixture_min = 2.7V
V_fixture_max = 3.6V
0s        3.3V       2.7V       3.6V
1.9ns     3.313V     2.7V       3.418V
2.1ns     3.312V     2.7V       3.078V
2.7ns     3.089V     2.708V     854.3mV
3.4ns     1.699V     2.709V     540.7mV
3.8ns     1.001V     2.708V     512.3mV
4.3ns     737.8mV    2.666V     494.8mV
7.3ns     568.1mV    1.163V     483.1mV
9ns       555.3mV    890.6mV    484.9mV
29.9ns    547.3mV    718.6mV    486.3mV
| Removed startup time: 0s 0s 0s  .
| Removed end time: 29.9ns.
[Rising Waveform]
R_fixture   = 50.0
V_fixture   = 0V
V_fixture_min = 0V
V_fixture_max = 0V
0s        587.5nV    409.7nV    -436.1nV
1.9ns     -7.945mV   769nV      96.19mV
2.6ns     97.02mV    184uV      1.858V
3ns       585.8mV    -1.664mV   2.671V
4.1ns     2.085V     6.148mV    3.043V
4.5ns     2.407V     75.27mV    3.073V
5.3ns     2.603V     347.4mV    3.104V
8.1ns     2.73V      1.553V     3.128V
9.9ns     2.742V     1.86V      3.13V
29.9ns    2.748V     2.008V     3.131V
| Removed startup time: 0s 0s 0s  .
| Removed end time: 18.9ns.
[Falling Waveform]
R_fixture   = 50.0
V_fixture   = 0V
V_fixture_min = 0V
V_fixture_max = 0V
0s        2.748V     2.008V     3.131V
1.6ns     2.736V     2.008V     2.948V
1.8ns     2.666V     2.008V     2.516V
2.3ns     2.169V     2.011V     309.4mV
2.6ns     1.376V     2.001V     24.52mV
3ns       315.5mV    1.868V     3.912mV
3.2ns     87.99mV    1.755V     3.215mV
4.6ns     2.461mV    377.5mV    1.455mV
5.4ns     1.687mV    27.03mV    1.055mV
18.9ns    10.56uV    106.3uV    2.616uV
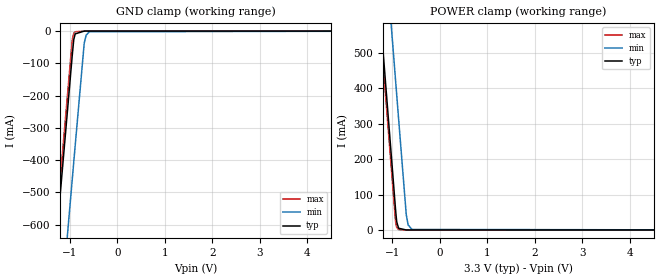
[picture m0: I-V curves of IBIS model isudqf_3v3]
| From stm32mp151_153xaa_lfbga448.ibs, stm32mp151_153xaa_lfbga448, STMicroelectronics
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[Model]   isudqf_3v3
Model_type Input
Polarity   Non-Inverting
Enable   Active-Low
| CAP_THRESHOLD on pad IOFT is "UDTCAPC" :
| Rising=20.00f vddiom   Falling=80.00f vddiom
| C_comp min and max val. don't necessarily correlate with the min and max pvt
| but are the smallest and greatest pad capacitance found.
| var   typ   min   max
C_comp   1.08465pF  1.07917pF  1.09313pF
|C_comp_pullup   494.14500fF  463.51000fF  489.77000fF
|C_comp_pulldown   590.50501fF  615.66002fF  603.36001fF
Vinl = 1.08V
Vinh = 2.16V
[Model Spec]
| TIME_THRESHOLD on pin ZIV11 is "CMOS" :
| Rising=40.00f vdd   Falling=60.00f vdd
Vinl 1.49460V 1.25060V 1.60860V
Vinh 1.49440V 1.25040V 1.60840V
| variable   typ   min   max
[Temperature Range] 25.0 140.0 -40.0
| variable   typ   min   max
[Voltage Range] 3.3V 2.7V 3.6V
| variable   typ   min   max
[POWER Clamp Reference] 3.3V 2.7V 3.6V
| variable   typ   min   max
[GND Clamp Reference] 0V 0V 0V
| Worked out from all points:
|   GND clamp passes 1 mA (typ) near -0.82 V on its own axis
|   POWER clamp passes 1 mA (typ) near -0.83 V on its own axis
[POWER Clamp]
-3.3V     4.079A     4.444A     4.043A
-1.27V    627.8mA    993.1mA    592.5mA
-1.16V    440.8mA    806.1mA    405.5mA
-1.09V    321.8mA    687.1mA    286.5mA
-940mV    66.83mA    432.1mA    31.5mA
-930mV    49.83mA    415.1mA    19.15mA
-910mV    22.88mA    381.1mA    7.077mA
-870mV    4.823mA    313.1mA    966.5uA
-710mV    9.522uA    43.89mA    336.9nA
-670mV    2.008uA    14.27mA    46.23nA
-590mV    89.43nA    1.508mA    968.7pA
6.6V      0A         0A         0A
[GND Clamp]
-3.3V     -4.067A    -4.452A    -4.019A
-1.49V    -990.4mA   -1.375A    -942.4mA
-1.27V    -616.4mA   -1.001A    -568.4mA
-1.1V     -327.4mA   -711.9mA   -279.4mA
-960mV    -89.41mA   -473.9mA   -41.39mA
-950mV    -72.41mA   -456.9mA   -25.65mA
-920mV    -26.33mA   -405.9mA   -6.567mA
-890mV    -8.748mA   -354.9mA   -2.091mA
-700mV    -45.74uA   -37.93mA   -12.71uA
-660mV    -15.26uA   -12.77mA   -7.471uA
-590mV    -5.248uA   -2.109mA   -4.907uA
6.6V      204pA      79.19nA    53.83pA
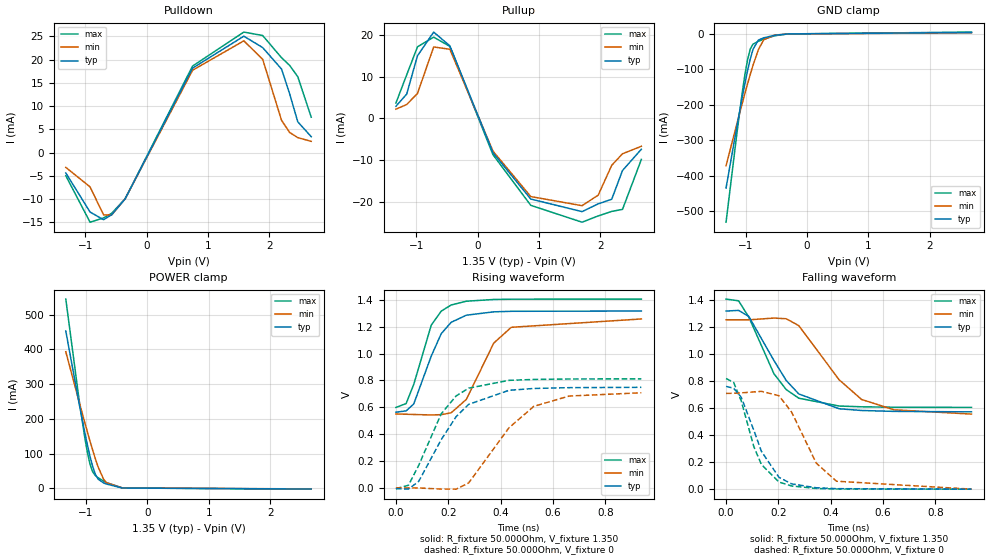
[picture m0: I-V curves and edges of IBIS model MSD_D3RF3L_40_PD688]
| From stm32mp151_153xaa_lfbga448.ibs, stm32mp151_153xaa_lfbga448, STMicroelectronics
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[Model] MSD_D3RF3L_40_PD688
Model_type   I/O
C_comp 2.452pF   2.367pF   2.576pF
Vinh = 810.000mV
Vinl = 540.000mV
Vmeas = 675.000mV
Vref = 675.000mV
[Model Spec]
Vinh   810.000mV   777.000mV   860.000mV
Vinl   540.000mV   507.000mV   590.000mV
Vmeas   675.000mV   642.000mV   725.000mV
Vref   675.000mV   642.000mV   725.000mV
[Temperature Range]   25.000   125.000   -40.000
[Voltage Range]   1.350V   1.283V   1.450V
[GND Clamp Reference]   0.00V   0.00V   0.00V
[Pulldown Reference]   0.00V   0.00V   0.00V
[POWER Clamp Reference]   1.350V   1.283V   1.450V
[Pullup Reference]   1.350V   1.283V   1.450V
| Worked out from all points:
|   slope of the pulldown table from 0 to 0.203 V, typ, clamps not added: 35.7 ohm
|   slope of the pullup table from 0 to 0.203 V, typ, clamps not added: 29.7 ohm
|   GND clamp passes 1 mA (typ) near -0.40 V on its own axis
|   POWER clamp passes 1 mA (typ) near -0.41 V on its own axis
|   rising waveform, R_fixture 50.000Ohm, V_fixture 1.350: 20-80 % time 90ps typ, 110ps min, 77.7ps max; typ from 0.564 V to 1.32 V
|   rising waveform, R_fixture 50.000Ohm, V_fixture 0: 20-80 % time 145ps typ, 169ps min, 126ps max; typ from -0.005 V to 0.749 V
|   falling waveform, R_fixture 50.000Ohm, V_fixture 1.350: 20-80 % time 144ps typ, 172ps min, 123ps max; typ from 1.32 V to 0.573 V
|   falling waveform, R_fixture 50.000Ohm, V_fixture 0: 20-80 % time 96.1ps typ, 113ps min, 83.2ps max; typ from 0.762 V to 0 V
[GND Clamp]
-1.318V   -434mA     -371.3mA   -530.2mA
-1.142V   -261.5mA   -253.5mA   -281.3mA
-1.055V   -179mA     -196mA     -166.2mA
-1.011V   -139.8mA   -167.8mA   -115.1mA
-966.7mV  -103mA     -140.4mA   -72.11mA
-922.7mV  -70.13mA   -113.7mA   -42.44mA
-878.8mV  -43.47mA   -88.39mA   -29mA
-790.9mV  -17.29mA   -44.25mA   -20.79mA
-703mV    -11.11mA   -16.27mA   -15.06mA
-527.3mV  -4.042mA   -3.425mA   -5.39mA
-307.6mV  -133.2uA   -195.4uA   -121.4uA
2.68V     3.865mA    3.009mA    5.016mA
[Power Clamp]
-1.33V    453.1mA    393.5mA    545.2mA
-1.111V   242.6mA    247.9mA    251.8mA
-1.023V   163mA      190.9mA    148.8mA
-978.8mV  125.7mA    162.9mA    104.3mA
-934.9mV  91.65mA    135.6mA    68.75mA
-890.9mV  62.25mA    109.3mA    47.1mA
-847mV    39.9mA     84.29mA    36.58mA
-803mV    26.52mA    61.46mA    30.46mA
-715.1mV  15.81mA    26.66mA    20.93mA
-671.2mV  12.58mA    16.56mA    16.75mA
-407.6mV  927uA      1.209mA    1.127mA
2.668V    -1.945mA   -1.621mA   -2.312mA
[Pulldown]
-1.318V   -4.4mA     -3.2mA     -5mA
-922.7mV  -12.81mA   -7.4mA     -14.99mA
-703mV    -14.46mA   -13.41mA   -14.07mA
-571.2mV  -13.39mA   -13.44mA   -13.08mA
-351.5mV  -9.978mA   -9.961mA   -9.956mA
747mV     18.14mA    17.69mA    18.59mA
1.582V    25.02mA    24.02mA    25.9mA
1.889V    22.57mA    20.05mA    25.16mA
2.197V    17.93mA    6.9mA      20.38mA
2.329V    12.6mA     4.3mA      18.73mA
2.461V    6.6mA      3.2mA      16.3mA
2.68V     3.4mA      2.4mA      7.6mA
[Pullup]
-1.33V    2.9mA      2.205mA    3.679mA
-1.155V   5.8mA      3.31mA     10.41mA
-978.8mV  15mA       5.977mA    17.14mA
-715.1mV  20.68mA    17.11mA    19.47mA
-451.5mV  17.38mA    16.56mA    17.25mA
251.5mV   -8.25mA    -7.869mA   -8.718mA
866.7mV   -19.34mA   -18.75mA   -20.85mA
1.702V    -22.36mA   -20.93mA   -24.89mA
1.965V    -20.5mA    -18.41mA   -23.39mA
2.185V    -19.39mA   -11.26mA   -22.3mA
2.361V    -12.5mA    -8.49mA    -21.82mA
2.668V    -7.4mA     -6.695mA   -9.848mA
[Ramp]
R_load=50.000Ohm
dV/dt_r   447.570mV/117.500ps  424.409mV/141.500ps  483.060mV/102.000ps
dV/dt_f   447.570mV/120.000ps  424.409mV/144.500ps  483.060mV/104.000ps
[Rising waveform]
R_fixture=50.000Ohm
V_fixture=1.350
V_fixture_min=1.283
V_fixture_max=1.450
0s        563.5mV    550.6mV    599mV
39ps      573.6mV    548.5mV    627.7mV
68ps      624.5mV    546.6mV    769.3mV
135ps     980.6mV    543.1mV    1.211V
173ps     1.147V     545.4mV    1.315V
211ps     1.232V     559mV      1.361V
269ps     1.285V     658.7mV    1.389V
374ps     1.31V      1.078V     1.402V
441ps     1.314V     1.195V     1.404V
938ps     1.316V     1.257V     1.405V
[Rising waveform]
R_fixture=50.000Ohm
V_fixture=0
0s        -5.262mV   806.4uV    -4.884mV
48ps      -7.836mV   912uV      20.33mV
87ps      49.05mV    156.6uV    168.3mV
173ps     359.2mV    -8.058mV   551.5mV
230ps     530.3mV    -8.731mV   684.3mV
278ps     622mV      37.41mV    742.5mV
432ps     726.4mV    447.5mV    800.5mV
527ps     740.2mV    607.1mV    807.3mV
662ps     746.1mV    683.8mV    810.6mV
938ps     748.7mV    708.2mV    811.7mV
[Falling waveform]
R_fixture=50.000Ohm
V_fixture=1.350
V_fixture_min=1.283
V_fixture_max=1.450
0s        1.321V     1.256V     1.41V
48ps      1.326V     1.256V     1.397V
87ps      1.281V     1.256V     1.276V
183ps     954.2mV    1.269V     856.1mV
230ps     806.2mV    1.264V     738.5mV
278ps     706.1mV    1.213V     674.6mV
432ps     596.4mV    811.8mV    616.7mV
518ps     583.5mV    665.3mV    610.9mV
642ps     576.9mV    588.5mV    607.7mV
938ps     573.4mV    556.9mV    606.5mV
[Falling waveform]
R_fixture=50.000Ohm
V_fixture=0
0s        762.3mV    710.3mV    820.8mV
29ps      748.6mV    711.4mV    791.8mV
58ps      681.8mV    714.1mV    654.6mV
106ps     437.7mV    721.6mV    316.5mV
135ps     281.3mV    725.6mV    183.3mV
202ps     88.25mV    693.3mV    53.38mV
250ps     39.64mV    573.7mV    23.75mV
345ps     10.16mV    192.6mV    5.149mV
422ps     3.675mV    58.85mV    1.523mV
938ps     21.19uV    197.6uV    -6.205uV
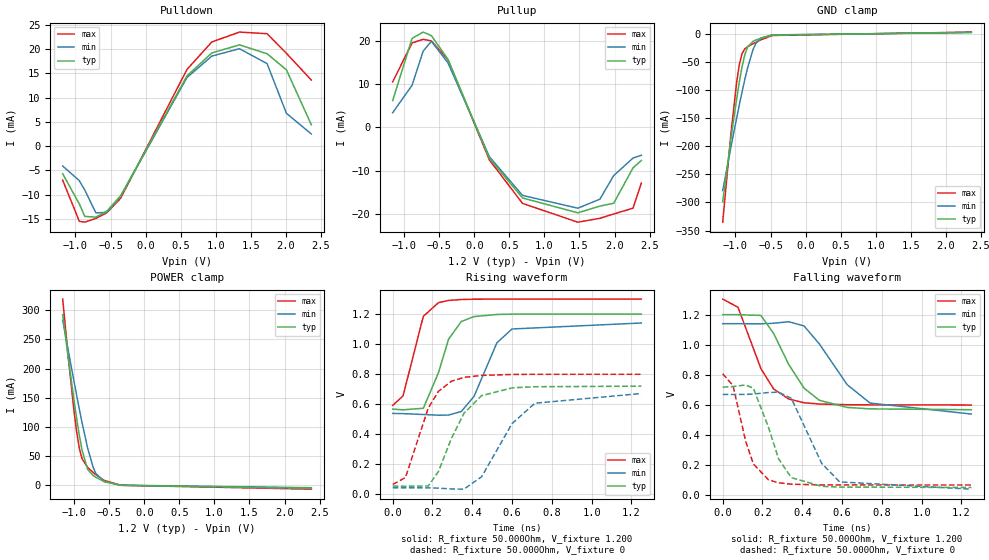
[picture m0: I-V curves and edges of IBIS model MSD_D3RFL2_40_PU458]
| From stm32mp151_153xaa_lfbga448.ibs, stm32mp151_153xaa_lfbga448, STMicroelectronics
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[Model] MSD_D3RFL2_40_PU458
Model_type   I/O
C_comp 2.406pF   2.319pF   2.532pF
Vinh = 820.000mV
Vinl = 380.000mV
Vmeas = 600.000mV
Vref = 600.000mV
[Model Spec]
Vinh   820.000mV   790.000mV   870.000mV
Vinl   380.000mV   350.000mV   430.000mV
Vmeas   600.000mV   570.000mV   650.000mV
Vref   600.000mV   570.000mV   650.000mV
[Temperature Range]   25.000   125.000   -40.000
[Voltage Range]   1.200V   1.140V   1.300V
[GND Clamp Reference]   0.00V   0.00V   0.00V
[Pulldown Reference]   0.00V   0.00V   0.00V
[POWER Clamp Reference]   1.200V   1.140V   1.300V
[Pullup Reference]   1.200V   1.140V   1.300V
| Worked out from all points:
|   slope of the pulldown table from 0 to 0.18 V, typ, clamps not added: 35.6 ohm
|   slope of the pullup table from 0 to 0.18 V, typ, clamps not added: 29.6 ohm
|   GND clamp passes 1 mA (typ) near -0.40 V on its own axis
|   POWER clamp passes 1 mA (typ) near -0.41 V on its own axis
|   rising waveform, R_fixture 50.000Ohm, V_fixture 1.200: 20-80 % time 90.4ps typ, 119ps min, 76.6ps max; typ from 0.564 V to 1.2 V
|   rising waveform, R_fixture 50.000Ohm, V_fixture 0: 20-80 % time 143ps typ, 177ps min, 120ps max; typ from 0.05 V to 0.718 V
|   falling waveform, R_fixture 50.000Ohm, V_fixture 1.200: 20-80 % time 164ps typ, 205ps min, 132ps max; typ from 1.2 V to 0.567 V
|   falling waveform, R_fixture 50.000Ohm, V_fixture 0: 20-80 % time 103ps typ, 128ps min, 85.7ps max; typ from 0.717 V to 0.049 V
[GND Clamp]
-1.182V   -299mA     -279mA     -335.2mA
-1.064V   -186.9mA   -201.3mA   -176.9mA
-984.9mV  -117.5mA   -151.2mA   -88.11mA
-945.5mV  -86.15mA   -126.9mA   -55.31mA
-906.1mV  -58.77mA   -103.6mA   -35.22mA
-866.7mV  -37.28mA   -81.4mA    -26.82mA
-827.3mV  -23.51mA   -60.86mA   -23.06mA
-748.5mV  -13.37mA   -27.9mA    -17.67mA
-709.1mV  -11.21mA   -17.31mA   -15.18mA
-630.3mV  -7.712mA   -7.374mA   -10.51mA
-472.7mV  -2.381mA   -2.076mA   -3.096mA
2.364V    2.48mA     2.095mA    2.917mA
[Power Clamp]
-1.164V   292.1mA    282.5mA    318.8mA
-1.085V   218.4mA    230.8mA    219.7mA
-1.006V   148.3mA    180mA      130.8mA
-966.7mV  115.6mA    155.1mA    93.04mA
-927.3mV  85.92mA    130.8mA    63.68mA
-887.9mV  60.21mA    107.3mA    45.58mA
-809.1mV  27.67mA    64.23mA    30.9mA
-730.3mV  16.91mA    31.08mA    22.23mA
-690.9mV  13.83mA    20.26mA    18.38mA
-572.7mV  6.582mA    6.523mA    8.677mA
-336.4mV  195.4uA    370.9uA    217.1uA
2.382V    -4.955mA   -3.949mA   -6.434mA
[Pulldown]
-1.182V   -5.7mA     -4.1mA     -7mA
-945.5mV  -11.88mA   -7.1mA     -15.48mA
-866.7mV  -14.47mA   -9.06mA    -15.66mA
-709.1mV  -14.62mA   -13.73mA   -14.89mA
-551.5mV  -13.37mA   -13.66mA   -13.72mA
-354.6mV  -10.22mA   -10.29mA   -10.71mA
590.9mV   14.46mA    14.13mA    15.79mA
945.5mV   19.18mA    18.53mA    21.44mA
1.339V    20.84mA    20.05mA    23.47mA
1.733V    19.01mA    16.98mA    23.14mA
2.009V    15.7mA     6.75mA     19.1mA
2.364V    4.4mA      2.5mA      13.6mA
[Pullup]
-1.164V   6.2mA      3.409mA    10.51mA
-887.9mV  20.5mA     9.715mA    19.46mA
-730.3mV  21.96mA    17.56mA    20.29mA
-612.1mV  21.14mA    19.85mA    19.93mA
-375.8mV  15.67mA    14.87mA    15.59mA
215.2mV   -7.104mA   -6.743mA   -7.481mA
687.9mV   -16.23mA   -15.64mA   -17.48mA
1.476V    -19.65mA   -18.59mA   -21.81mA
1.791V    -18.11mA   -16.51mA   -20.92mA
1.988V    -17.45mA   -11.08mA   -19.92mA
2.264V    -9.3mA     -7.043mA   -18.58mA
2.382V    -7.6mA     -6.395mA   -12.82mA
[Ramp]
R_load=50.000Ohm
dV/dt_r   390.501mV/117.500ps  370.728mV/148.500ps  429.906mV/98.000ps
dV/dt_f   390.501mV/134.500ps  370.638mV/167.500ps  429.906mV/108.500ps
[Rising waveform]
R_fixture=50.000Ohm
V_fixture=1.200
V_fixture_min=1.140
V_fixture_max=1.300
0s        564.4mV    535.5mV    589.2mV
52ps      559.4mV    534.1mV    652.7mV
154ps     570.1mV    528.3mV    1.185V
230ps     807.7mV    523.5mV    1.276V
281ps     1.032V     524.6mV    1.291V
345ps     1.15V      548.4mV    1.297V
409ps     1.183V     649.8mV    1.299V
524ps     1.197V     1.008V     1.3V
600ps     1.199V     1.1V       1.3V
1.25ns    1.2V       1.14V      1.3V
[Rising waveform]
R_fixture=50.000Ohm
V_fixture=0
0s        49.98mV    38.09mV    60.56mV
64ps      48.65mV    38.44mV    106.7mV
179ps     50.64mV    38.02mV    572.1mV
230ps     147.4mV    36.01mV    683.1mV
294ps     365.1mV    30.6mV     749.8mV
358ps     536.3mV    29.14mV    776.4mV
447ps     654.2mV    112.1mV    789.7mV
600ps     706.4mV    467.4mV    796mV
715ps     713.9mV    603.7mV    797mV
1.25ns    717.7mV    668.4mV    797.3mV
[Falling waveform]
R_fixture=50.000Ohm
V_fixture=1.200
V_fixture_min=1.140
V_fixture_max=1.300
0s        1.2V       1.14V      1.304V
77ps      1.2V       1.14V      1.249V
192ps     1.195V     1.139V     841.2mV
256ps     1.075V     1.143V     705mV
332ps     868.3mV    1.153V     638mV
409ps     710.9mV    1.125V     613.5mV
486ps     629.8mV    1.005V     605mV
626ps     582.4mV    733.8mV    600.5mV
741ps     572.6mV    611.5mV    599.5mV
1.25ns    567.2mV    538.3mV    598.5mV
[Falling waveform]
R_fixture=50.000Ohm
V_fixture=0
0s        717.2mV    668.9mV    806.5mV
52ps      721.5mV    668.6mV    727.6mV
115ps     731.9mV    669.2mV    358.8mV
154ps     710.6mV    671.7mV    206.4mV
230ps     450.8mV    681.6mV    100.3mV
281ps     239.9mV    684.2mV    80.56mV
345ps     114.7mV    643.1mV    71.12mV
498ps     56.99mV    209.1mV    66.24mV
588ps     51.91mV    86.38mV    65.94mV
1.25ns    49.33mV    38.04mV    65.78mV
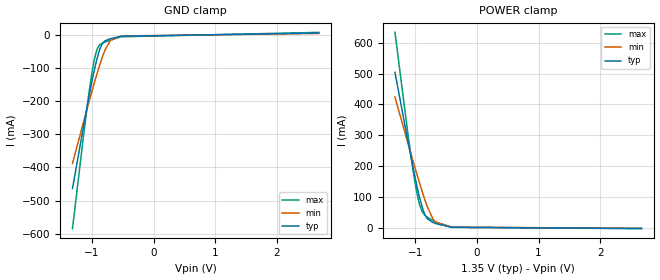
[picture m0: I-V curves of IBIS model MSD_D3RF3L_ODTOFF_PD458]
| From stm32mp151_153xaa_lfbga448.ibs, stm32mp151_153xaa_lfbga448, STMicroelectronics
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[Model] MSD_D3RF3L_ODTOFF_PD458
Model_type   Input
C_comp 2.392pF   2.308pF   2.516pF
Vinh = 810.000mV
Vinl = 540.000mV
[Temperature Range]   25.000   125.000   -40.000
[Voltage Range]   1.350V   1.283V   1.450V
[GND Clamp Reference]   0.00V   0.00V   0.00V
[POWER Clamp Reference]   1.350V   1.283V   1.450V
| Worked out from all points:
|   GND clamp passes 1 mA (typ) near -0.40 V on its own axis
|   POWER clamp passes 1 mA (typ) near -0.41 V on its own axis
[GND Clamp]
-1.318V   -463.7mA   -388.3mA   -584.7mA
-1.142V   -279.4mA   -265.2mA   -309.6mA
-1.055V   -190.8mA   -204.9mA   -181.5mA
-1.011V   -148.6mA   -175.4mA   -124.3mA
-966.7mV  -109.1mA   -146.6mA   -76.74mA
-922.7mV  -73.78mA   -118.7mA   -44.55mA
-878.8mV  -45.27mA   -92.08mA   -30.35mA
-834.9mV  -26.66mA   -67.46mA   -25.12mA
-790.9mV  -17.78mA   -45.78mA   -21.7mA
-703mV    -11.37mA   -16.62mA   -15.64mA
-527.3mV  -4.072mA   -3.428mA   -5.49mA
2.68V     5.843mA    4.543mA    7.594mA
[Power Clamp]
-1.33V    503.9mA    423.7mA    633.8mA
-1.111V   270.7mA    267.7mA    290.1mA
-1.023V   181.3mA    206.5mA    168.4mA
-978.8mV  139.2mA    176.4mA    117mA
-934.9mV  100.6mA    146.9mA    76.74mA
-890.9mV  67.57mA    118.4mA    52.35mA
-847mV    42.82mA    91.21mA    40.43mA
-803mV    28.26mA    66.31mA    33.41mA
-715.1mV  16.65mA    28.39mA    22.58mA
-671.2mV  13.15mA    17.43mA    17.92mA
-407.6mV  908uA      1.187mA    1.112mA
2.668V    -2.939mA   -2.446mA   -3.502mA
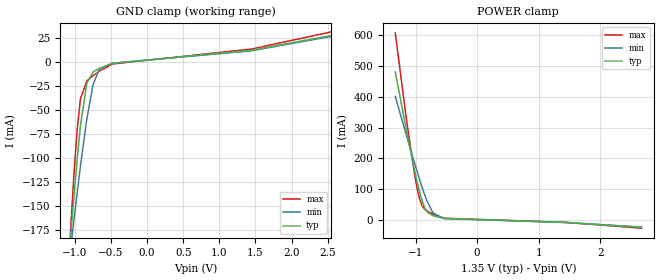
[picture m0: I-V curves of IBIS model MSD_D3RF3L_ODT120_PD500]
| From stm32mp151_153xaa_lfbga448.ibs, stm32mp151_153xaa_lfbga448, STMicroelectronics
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[Model] MSD_D3RF3L_ODT120_PD500
Model_type   Input
C_comp 2.367pF   2.289pF   2.457pF
Vinh = 810.000mV
Vinl = 540.000mV
[Temperature Range]   25.000   125.000   -40.000
[Voltage Range]   1.350V   1.283V   1.450V
[GND Clamp Reference]   0.00V   0.00V   0.00V
[POWER Clamp Reference]   1.350V   1.283V   1.450V
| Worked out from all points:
|   GND clamp passes 1 mA (typ) near -0.43 V on its own axis
|   POWER clamp passes 1 mA (typ) near -0.31 V on its own axis
[GND Clamp]
-1.318V   -446.6mA   -371.5mA   -565.1mA
-1.098V   -221.4mA   -221.3mA   -229.8mA
-1.055V   -178.7mA   -192mA     -169.1mA
-1.011V   -137.9mA   -163.3mA   -114.4mA
-966.7mV  -99.87mA   -135.4mA   -69.19mA
-922.7mV  -66.37mA   -108.4mA   -38.32mA
-834.9mV  -22.23mA   -59.53mA   -20.11mA
-747mV    -10.63mA   -23.46mA   -14.58mA
-659.1mV  -6.88mA    -7.363mA   -9.753mA
-483.3mV  -1.859mA   -1.57mA    -2.414mA
1.45V     11.98mA    11.35mA    13.2mA
2.68V     28.98mA    28.02mA    33mA
[Power Clamp]
-1.33V    481.6mA    401.9mA    608.3mA
-1.155V   297.8mA    279.4mA    336.3mA
-1.023V   166.7mA    189.6mA    156.3mA
-978.8mV  126.9mA    160.5mA    107mA
-934.9mV  90.98mA    132.1mA    68.24mA
-890.9mV  60.5mA     104.8mA    45.04mA
-847mV    37.6mA     79.23mA    34.14mA
-803mV    24.22mA    56.28mA    28.04mA
-715.1mV  14.16mA    22.86mA    18.83mA
-539.4mV  4.906mA    4.587mA    5.824mA
1.438V    -7.686mA   -8.227mA   -7.847mA
2.668V    -23.85mA   -23.11mA   -26.57mA
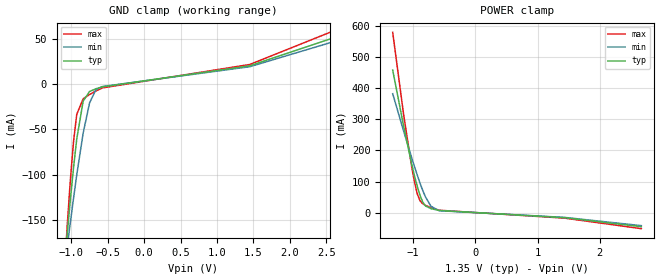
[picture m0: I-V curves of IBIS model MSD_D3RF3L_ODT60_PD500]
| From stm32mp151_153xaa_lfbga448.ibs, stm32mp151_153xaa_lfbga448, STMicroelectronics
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[Model] MSD_D3RF3L_ODT60_PD500
Model_type   Input
C_comp 2.364pF   2.314pF   2.432pF
Vinh = 810.000mV
Vinl = 540.000mV
[Temperature Range]   25.000   125.000   -40.000
[Voltage Range]   1.350V   1.283V   1.450V
[GND Clamp Reference]   0.00V   0.00V   0.00V
[POWER Clamp Reference]   1.350V   1.283V   1.450V
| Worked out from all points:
|   GND clamp passes 1 mA (typ) near -0.45 V on its own axis
|   POWER clamp passes 1 mA (typ) near -0.18 V on its own axis
[GND Clamp]
-1.318V   -429.7mA   -356.6mA   -545mA
-1.098V   -209mA     -209.6mA   -216.6mA
-1.055V   -167.5mA   -181.1mA   -158.6mA
-1.011V   -128.3mA   -153.2mA   -106.7mA
-966.7mV  -92.29mA   -126.2mA   -63.26mA
-922.7mV  -60.63mA   -100.2mA   -33.25mA
-834.9mV  -18.6mA    -54.06mA   -16.01mA
-747mV    -7.927mA   -20.54mA   -11.32mA
-659.1mV  -4.946mA   -5.825mA   -7.33mA
-571.2mV  -2.795mA   -2.439mA   -3.978mA
1.45V     20.49mA    19.49mA    21.96mA
2.68V     53.65mA    49.15mA    61.77mA
[Power Clamp]
-1.33V    458.8mA    382.8mA    580.3mA
-1.155V   279.2mA    262.8mA    316.3mA
-1.023V   154.5mA    175.6mA    145.2mA
-978.8mV  117.7mA    147.6mA    97.68mA
-934.9mV  84.41mA    120.6mA    60.31mA
-890.9mV  55.73mA    94.97mA    38.31mA
-847mV    33.99mA    71.34mA    28.48mA
-803mV    21.48mA    50.47mA    23.37mA
-715.1mV  12.76mA    20.52mA    15.9mA
-583.3mV  6.874mA    6.128mA    7.614mA
1.438V    -16.32mA   -15.51mA   -17.88mA
2.668V    -45.43mA   -42.02mA   -51.69mA
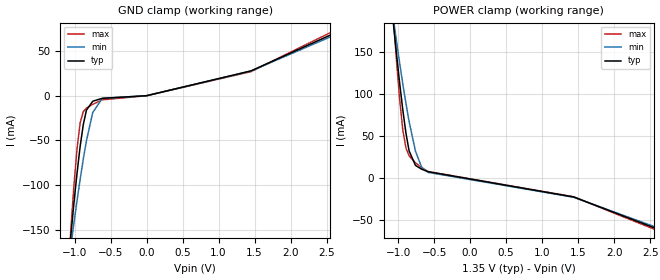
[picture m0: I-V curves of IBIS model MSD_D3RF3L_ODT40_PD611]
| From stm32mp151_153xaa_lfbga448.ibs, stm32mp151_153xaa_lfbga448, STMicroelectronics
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[Model] MSD_D3RF3L_ODT40_PD611
Model_type   Input
C_comp 2.377pF   2.337pF   2.429pF
Vinh = 810.000mV
Vinl = 540.000mV
[Temperature Range]   25.000   125.000   -40.000
[Voltage Range]   1.350V   1.283V   1.450V
[GND Clamp Reference]   0.00V   0.00V   0.00V
[POWER Clamp Reference]   1.350V   1.283V   1.450V
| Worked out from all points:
|   GND clamp passes 1 mA (typ) near -0.46 V on its own axis
|   POWER clamp passes 1 mA (typ) near -0.15 V on its own axis
[GND Clamp]
-1.318V   -415.9mA   -341.8mA   -534mA
-1.055V   -159.5mA   -170.8mA   -153.7mA
-1.011V   -122mA     -144mA     -103mA
-966.7mV  -87.43mA   -118.1mA   -60.21mA
-922.7mV  -56.97mA   -93.71mA   -30.51mA
-878.8mV  -32.3mA    -70.88mA   -17.83mA
-834.9mV  -16.15mA   -50.33mA   -13.84mA
-747mV    -6.168mA   -18.7mA    -9.66mA
-615.1mV  -2.936mA   -2.932mA   -4.62mA
200nV     3.769nA    3.556nA    3.916nA
1.45V     27.75mA    27.56mA    26.92mA
2.68V     72.44mA    70.18mA    75.64mA
[Power Clamp]
-1.33V    441.4mA    363.9mA    566.5mA
-1.067V   185.3mA    190.5mA    192.8mA
-1.023V   148mA      163.3mA    140.6mA
-978.8mV  113.1mA    137mA      93.76mA
-934.9mV  81.03mA    112mA      57mA
-890.9mV  53.12mA    88.52mA    35.52mA
-847mV    31.98mA    66.99mA    26.16mA
-759.1mV  14.8mA     31.7mA     17.94mA
-671.2mV  10.23mA    12.32mA    12.02mA
-583.3mV  7.275mA    6.493mA    7.501mA
1.438V    -22.85mA   -23.22mA   -22.63mA
2.668V    -63.34mA   -61.63mA   -65.25mA
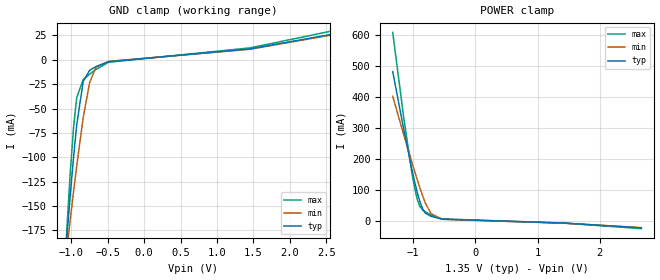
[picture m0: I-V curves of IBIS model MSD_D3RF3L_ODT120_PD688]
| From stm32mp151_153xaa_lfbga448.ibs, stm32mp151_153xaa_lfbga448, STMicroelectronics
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[Model] MSD_D3RF3L_ODT120_PD688
Model_type   Input
C_comp 2.410pF   2.297pF   2.501pF
Vinh = 810.000mV
Vinl = 540.000mV
[Temperature Range]   25.000   125.000   -40.000
[Voltage Range]   1.350V   1.283V   1.450V
[GND Clamp Reference]   0.00V   0.00V   0.00V
[POWER Clamp Reference]   1.350V   1.283V   1.450V
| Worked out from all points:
|   GND clamp passes 1 mA (typ) near -0.43 V on its own axis
|   POWER clamp passes 1 mA (typ) near -0.31 V on its own axis
[GND Clamp]
-1.318V   -447mA     -371.8mA   -565.7mA
-1.098V   -221.8mA   -221.5mA   -230.3mA
-1.055V   -179mA     -192.3mA   -169.5mA
-1.011V   -138.2mA   -163.6mA   -114.8mA
-966.7mV  -100.1mA   -135.6mA   -69.52mA
-922.7mV  -66.59mA   -108.6mA   -38.61mA
-834.9mV  -22.42mA   -59.67mA   -20.36mA
-747mV    -10.77mA   -23.58mA   -14.77mA
-659.1mV  -6.989mA   -7.454mA   -9.897mA
-483.3mV  -1.9mA     -1.613mA   -2.471mA
1.45V     11.19mA    10.73mA    12.17mA
2.68V     27.54mA    26.89mA    31.12mA
[Power Clamp]
-1.33V    482.1mA    402.4mA    608.8mA
-1.155V   298.2mA    279.8mA    336.8mA
-1.023V   166.9mA    189.9mA    156.7mA
-978.8mV  127.1mA    160.7mA    107.4mA
-934.9mV  91.21mA    132.3mA    68.57mA
-890.9mV  60.73mA    105mA      45.33mA
-847mV    37.8mA     79.43mA    34.4mA
-803mV    24.41mA    56.45mA    28.27mA
-715.1mV  14.29mA    22.99mA    19.01mA
-539.4mV  4.969mA    4.66mA     5.904mA
1.438V    -7.637mA   -8.158mA   -7.847mA
2.668V    -23.11mA   -22.5mA    -25.69mA
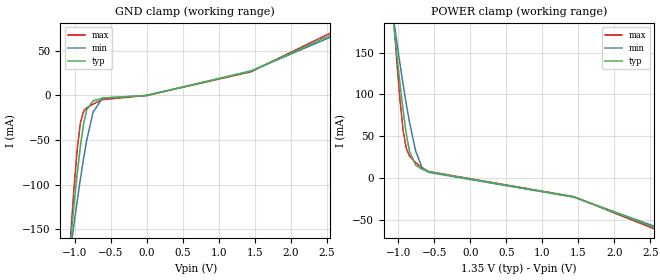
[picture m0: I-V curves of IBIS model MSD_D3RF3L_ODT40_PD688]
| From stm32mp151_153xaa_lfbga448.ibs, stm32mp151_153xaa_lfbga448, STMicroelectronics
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[Model] MSD_D3RF3L_ODT40_PD688
Model_type   Input
C_comp 2.390pF   2.349pF   2.443pF
Vinh = 810.000mV
Vinl = 540.000mV
[Temperature Range]   25.000   125.000   -40.000
[Voltage Range]   1.350V   1.283V   1.450V
[GND Clamp Reference]   0.00V   0.00V   0.00V
[POWER Clamp Reference]   1.350V   1.283V   1.450V
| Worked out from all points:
|   GND clamp passes 1 mA (typ) near -0.46 V on its own axis
|   POWER clamp passes 1 mA (typ) near -0.15 V on its own axis
[GND Clamp]
-1.318V   -416mA     -341.8mA   -534.1mA
-1.055V   -159.6mA   -170.8mA   -153.9mA
-1.011V   -122.1mA   -144mA     -103.2mA
-966.7mV  -87.5mA    -118.3mA   -60.27mA
-922.7mV  -57.04mA   -93.73mA   -30.64mA
-878.8mV  -32.36mA   -71mA      -17.95mA
-834.9mV  -16.2mA    -50.38mA   -13.96mA
-747mV    -6.214mA   -18.73mA   -9.754mA
-615.1mV  -2.968mA   -2.956mA   -4.678mA
200nV     3.727nA    3.518nA    3.869nA
1.45V     27.49mA    27.35mA    26.58mA
2.68V     72.01mA    69.8mA     75.02mA
[Power Clamp]
-1.33V    441.5mA    364mA      566.7mA
-1.067V   185.4mA    190.6mA    193mA
-1.023V   148.1mA    163.3mA    140.7mA
-978.8mV  113.2mA    137mA      93.89mA
-934.9mV  81.1mA     112mA      57.08mA
-890.9mV  53.09mA    88.57mA    35.59mA
-847mV    32.02mA    66.99mA    26.24mA
-759.1mV  14.82mA    31.75mA    18.01mA
-671.2mV  10.25mA    12.35mA    12.06mA
-583.3mV  7.269mA    6.514mA    7.534mA
1.438V    -22.84mA   -23.2mA    -22.63mA
2.668V    -63.1mA    -61.44mA   -64.92mA
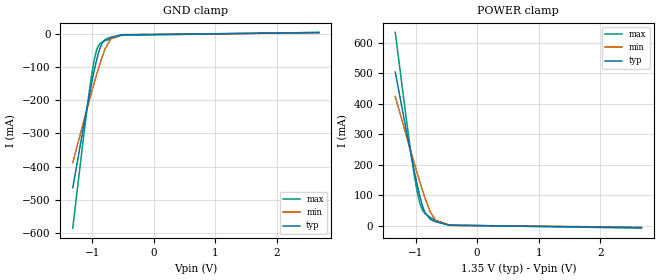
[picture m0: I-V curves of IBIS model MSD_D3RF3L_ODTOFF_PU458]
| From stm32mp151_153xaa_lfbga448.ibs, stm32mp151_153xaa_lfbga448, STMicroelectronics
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[Model] MSD_D3RF3L_ODTOFF_PU458
Model_type   Input
C_comp 2.396pF   2.311pF   2.520pF
Vinh = 810.000mV
Vinl = 540.000mV
[Temperature Range]   25.000   125.000   -40.000
[Voltage Range]   1.350V   1.283V   1.450V
[GND Clamp Reference]   0.00V   0.00V   0.00V
[POWER Clamp Reference]   1.350V   1.283V   1.450V
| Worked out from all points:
|   GND clamp passes 1 mA (typ) near -0.40 V on its own axis
|   POWER clamp passes 1 mA (typ) near -0.41 V on its own axis
[GND Clamp]
-1.318V   -463.6mA   -388.1mA   -584.6mA
-1.142V   -279.3mA   -265mA     -309.5mA
-1.055V   -190.7mA   -204.8mA   -181.4mA
-1.011V   -148.6mA   -175.4mA   -124.3mA
-966.7mV  -109.1mA   -146.5mA   -76.72mA
-922.7mV  -73.73mA   -118.6mA   -44.52mA
-878.8mV  -45.24mA   -92.02mA   -30.33mA
-834.9mV  -26.62mA   -67.4mA    -25.1mA
-790.9mV  -17.74mA   -45.74mA   -21.68mA
-703mV    -11.35mA   -16.58mA   -15.62mA
-527.3mV  -4.056mA   -3.405mA   -5.479mA
2.68V     2.907mA    2.466mA    3.446mA
[Power Clamp]
-1.33V    504mA      424mA      633.9mA
-1.155V   316.9mA    298.8mA    356.6mA
-1.067V   225.5mA    237.1mA    226.8mA
-1.023V   181.4mA    206.6mA    168.5mA
-978.8mV  139.3mA    176.5mA    117.1mA
-934.9mV  100.7mA    147mA      76.78mA
-890.9mV  67.63mA    118.4mA    52.39mA
-847mV    42.89mA    91.27mA    40.47mA
-759.1mV  21.09mA    44.98mA    27.74mA
-671.2mV  13.18mA    17.49mA    17.94mA
-451.5mV  1.885mA    2.129mA    2.378mA
2.668V    -5.732mA   -4.585mA   -7.384mA
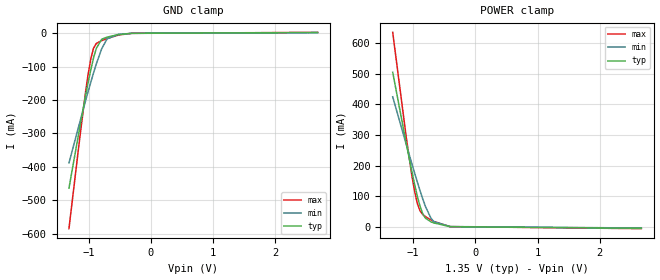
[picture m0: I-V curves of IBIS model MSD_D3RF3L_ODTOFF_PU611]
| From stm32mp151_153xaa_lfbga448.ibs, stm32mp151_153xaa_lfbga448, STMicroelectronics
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[Model] MSD_D3RF3L_ODTOFF_PU611
Model_type   Input
C_comp 2.442pF   2.356pF   2.566pF
Vinh = 810.000mV
Vinl = 540.000mV
[Temperature Range]   25.000   125.000   -40.000
[Voltage Range]   1.350V   1.283V   1.450V
[GND Clamp Reference]   0.00V   0.00V   0.00V
[POWER Clamp Reference]   1.350V   1.283V   1.450V
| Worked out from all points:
|   GND clamp passes 1 mA (typ) near -0.40 V on its own axis
|   POWER clamp passes 1 mA (typ) near -0.41 V on its own axis
[GND Clamp]
-1.318V   -464mA     -388.5mA   -585.3mA
-1.142V   -279.7mA   -265.4mA   -310mA
-1.055V   -191mA     -205.1mA   -181.8mA
-1.011V   -148.9mA   -175.5mA   -124.7mA
-966.7mV  -109.4mA   -146.7mA   -77.05mA
-922.7mV  -73.98mA   -118.8mA   -44.83mA
-878.8mV  -45.46mA   -92.2mA    -30.61mA
-790.9mV  -17.92mA   -45.89mA   -21.91mA
-703mV    -11.49mA   -16.69mA   -15.8mA
-527.3mV  -4.121mA   -3.461mA   -5.564mA
-307.6mV  -128.6uA   -188uA     -118.8uA
2.68V     2.18mA     1.85mA     2.585mA
[Power Clamp]
-1.33V    504.5mA    424.4mA    634.5mA
-1.111V   271.2mA    268.2mA    290.6mA
-1.023V   181.6mA    206.9mA    168.8mA
-978.8mV  139.6mA    176.8mA    117.4mA
-934.9mV  101mA      147.2mA    77.11mA
-890.9mV  67.86mA    118.6mA    52.68mA
-847mV    43.08mA    91.44mA    40.72mA
-803mV    28.49mA    66.55mA    33.68mA
-715.1mV  16.83mA    28.58mA    22.79mA
-671.2mV  13.31mA    17.59mA    18.09mA
-407.6mV  944.1uA    1.233mA    1.149mA
2.668V    -4.294mA   -3.435mA   -5.533mA
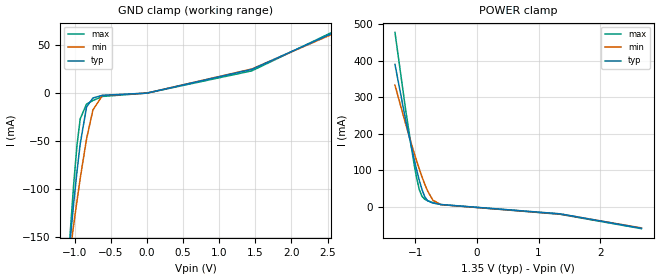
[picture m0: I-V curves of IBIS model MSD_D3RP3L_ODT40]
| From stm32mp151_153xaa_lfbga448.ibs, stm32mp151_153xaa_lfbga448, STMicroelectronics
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[Model] MSD_D3RP3L_ODT40
Model_type   Input
C_comp 2.176pF   2.140pF   2.223pF
Vinh = 810.000mV
Vinl = 540.000mV
[Temperature Range]   25.000   125.000   -40.000
[Voltage Range]   1.350V   1.283V   1.450V
[GND Clamp Reference]   0.00V   0.00V   0.00V
[POWER Clamp Reference]   1.350V   1.283V   1.450V
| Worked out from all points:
|   GND clamp passes 1 mA (typ) near -0.50 V on its own axis
|   POWER clamp passes 1 mA (typ) near -0.16 V on its own axis
[GND Clamp]
-1.318V   -385.3mA   -324.3mA   -478.1mA
-1.098V   -184.8mA   -187.8mA   -189.5mA
-1.055V   -148.1mA   -161.8mA   -139.1mA
-1.011V   -113.5mA   -136.4mA   -93.29mA
-966.7mV  -81.47mA   -112.1mA   -54.16mA
-922.7mV  -52.99mA   -88.94mA   -26.85mA
-834.9mV  -14.49mA   -47.83mA   -11.44mA
-747mV    -5.09mA    -17.61mA   -7.768mA
-615.1mV  -2.29mA    -2.496mA   -3.476mA
200nV     3.259nA    3.159nA    3.265nA
1.45V     24.73mA    25.12mA    23.18mA
2.68V     66.28mA    65.16mA    67.7mA
[Power Clamp]
-1.33V    390.1mA    333.3mA    478mA
-1.155V   236.2mA    225.7mA    263.4mA
-1.023V   132.6mA    149.4mA    119.5mA
-978.8mV  101.1mA    125.5mA    78.61mA
-934.9mV  71.97mA    102.9mA    46.57mA
-890.9mV  46.53mA    81.47mA    28.1mA
-847mV    27.37mA    61.63mA    20.3mA
-803mV    16.59mA    43.83mA    16.54mA
-715.1mV  9.851mA    17.72mA    11.29mA
-583.3mV  5.983mA    5.55mA     5.755mA
1.35V     -19.59mA   -20.01mA   -20.84mA
2.668V    -59.19mA   -58.28mA   -60.26mA
